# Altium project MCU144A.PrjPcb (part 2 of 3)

## Sheet MCU144A_SOM_Power.SchDoc: controlSOM Power
size 431 x 279 mm; Date: Not shown in title block; ApprovedBy: Not shown in title block; CheckedBy: Not shown in title block; Author: Not shown in title block; CompanyName: Not shown in title block; DrawnBy: Gustavo Martinez; Engineer: Not shown in title block; Organization: Not shown in title block; Address1: Not shown in title block; Address2: Not shown in title block; Address3: Not shown in title block; Address4: Not shown in title block; DocumentNumber: 6; Revision: Use project parameter SCH_Rev; SheetNumber: 5; SheetTotal: 8; PageSetup: Record=PageOptions¦CenterHorizontal=True¦CenterVertical=True¦PrintScale=1.00¦XCorrection=1.00¦YCorrection=1.00¦PrintKind=0¦BorderSize=5000000¦LeftOffset=0¦BottomOffset=0¦Orientation=2¦PaperLength=1000¦PaperWidth=1000¦Scale=100¦PaperSource=15¦PrintQuality=600¦MediaType=1¦DitherType=10¦PaperKind=Letter¦PrintScaleMode=1

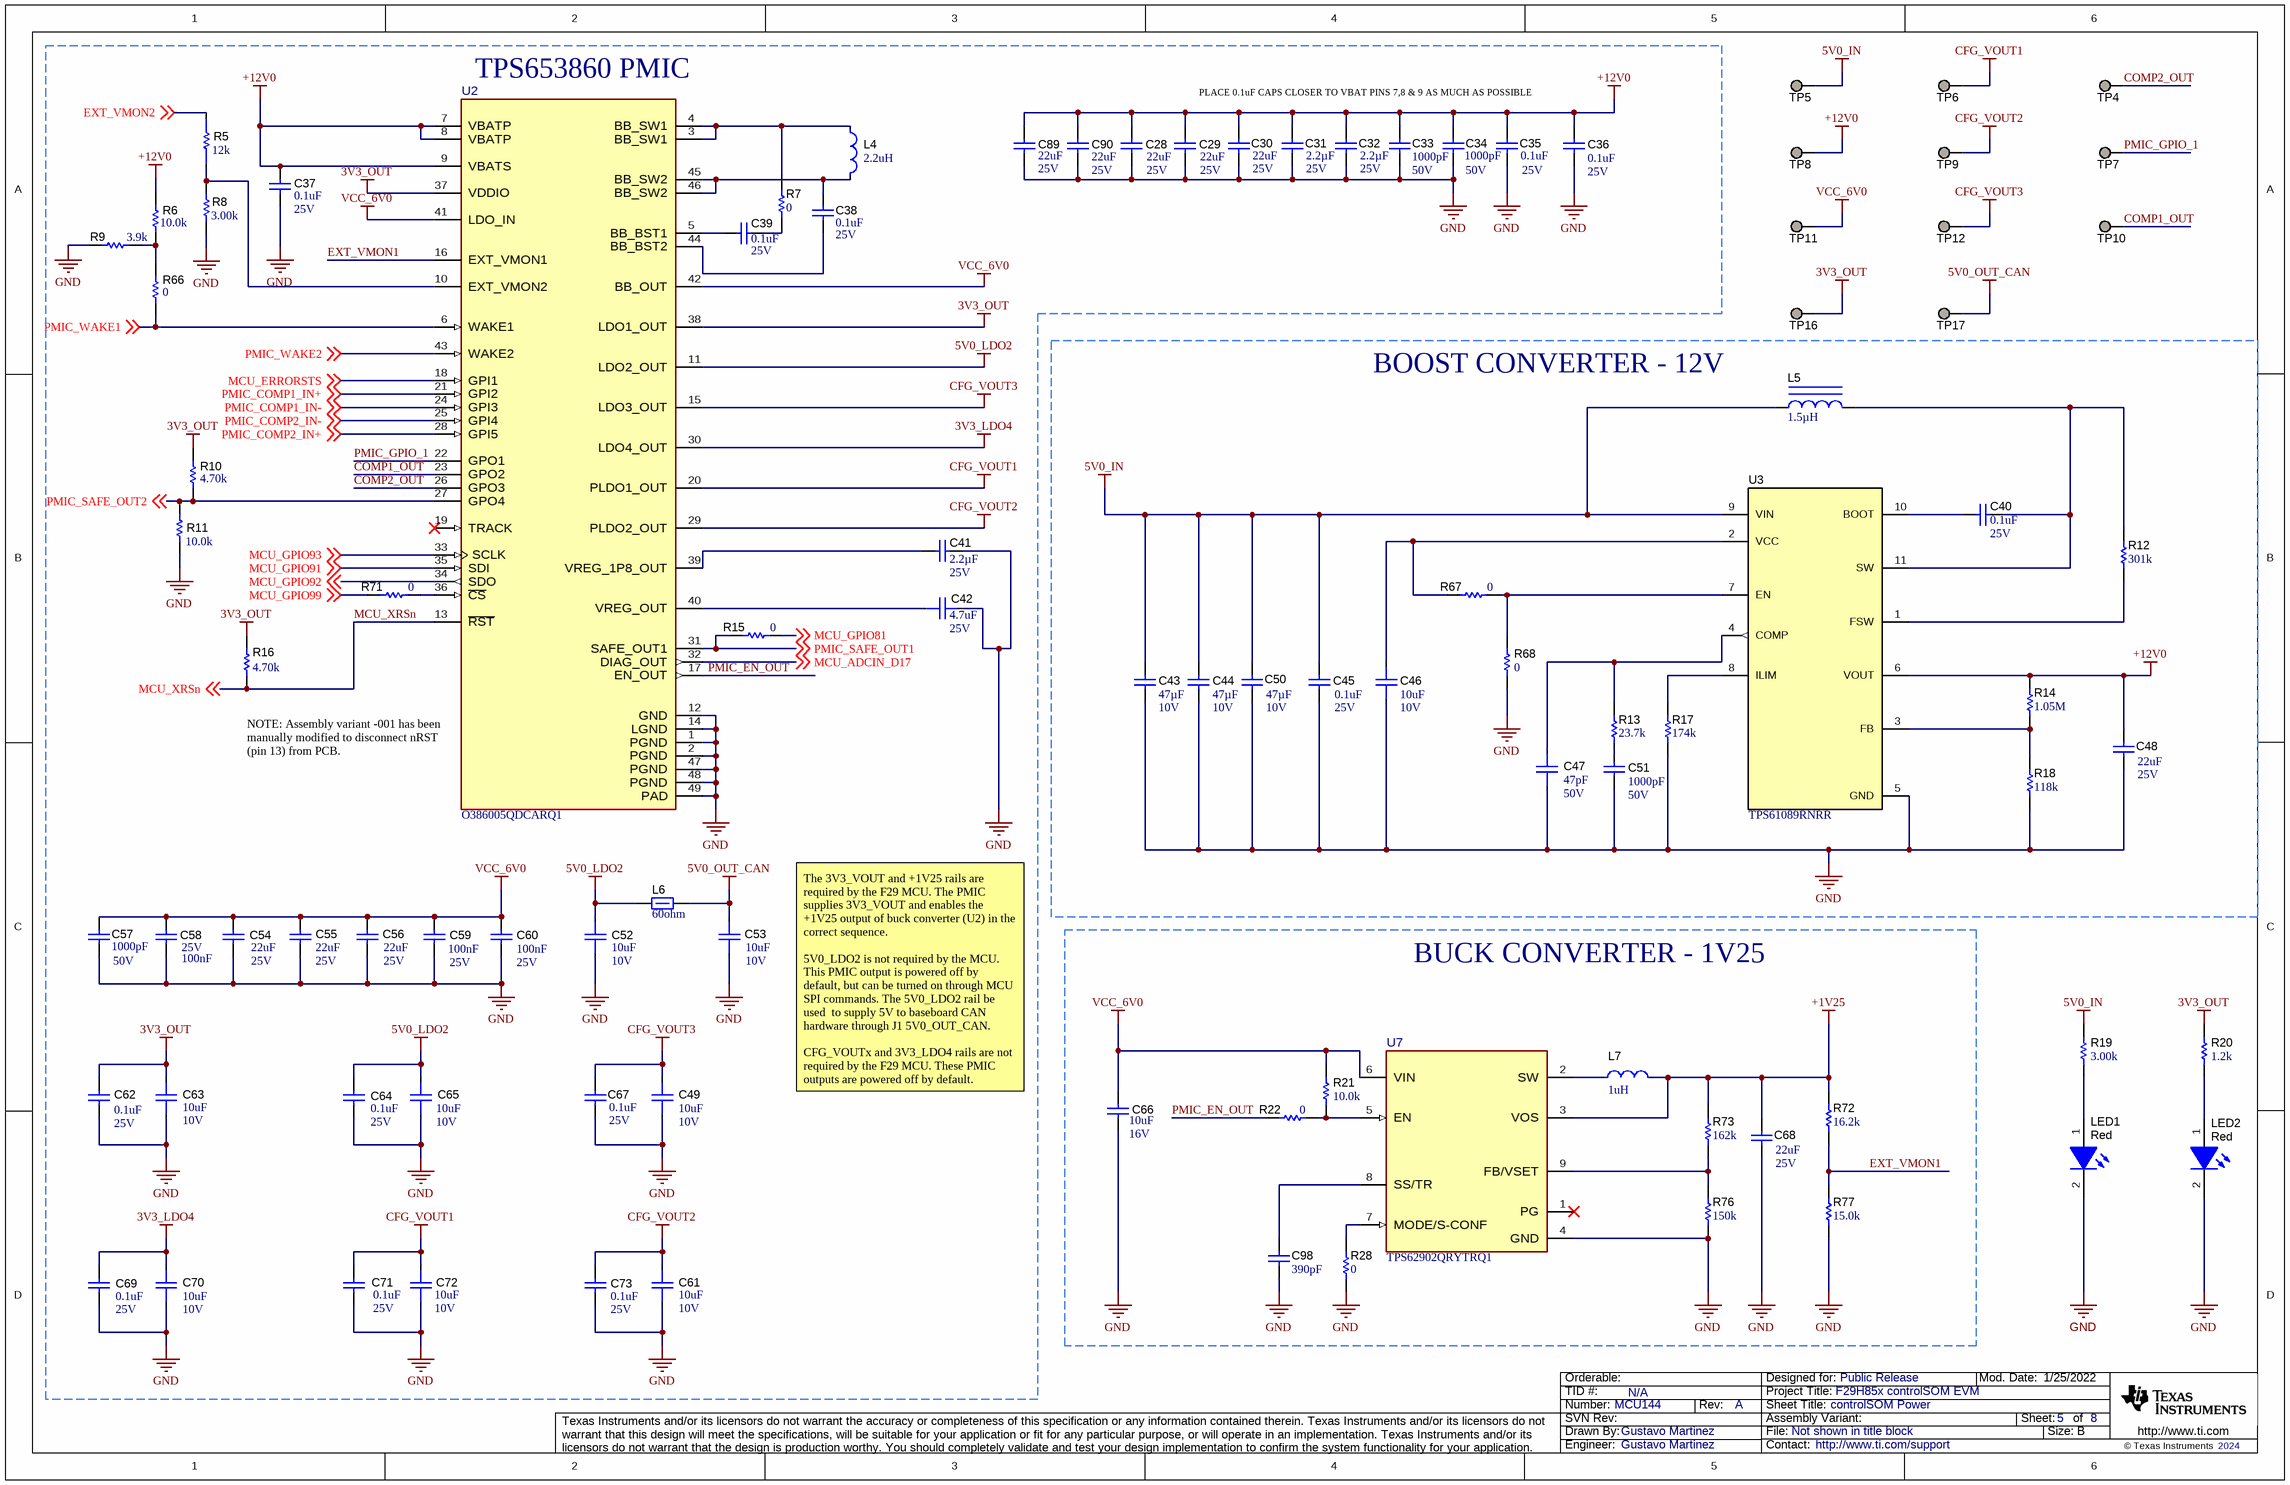
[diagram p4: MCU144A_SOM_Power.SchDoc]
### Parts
C28  VDC_V: 25V  ValueDisplayed: 22uF  [0805_HV]  (hidden comment: GRM21BR61E226ME44L)
C29  VDC_V: 25V  ValueDisplayed: 22uF  [0805_HV]  (hidden comment: GRM21BR61E226ME44L)
C30  VDC_V: 25V  ValueDisplayed: 22uF  [0805_HV]  (hidden comment: GRM21BR61E226ME44L)
C31  VDC_V: 25V  ValueDisplayed: 2.2µF  [0402]  (hidden comment: GRM155R61E225ME15D)
C32  VDC_V: 25V  ValueDisplayed: 2.2µF  [0402]  (hidden comment: GRM155R61E225ME15D)
C33  VDC_V: 50V  ValueDisplayed: 1000pF  [0402]  (hidden comment: GRM1555C1H102JA01D)
C34  VDC_V: 50V  ValueDisplayed: 1000pF  [0402]  (hidden comment: GRM1555C1H102JA01D)
C35  VDC_V: 25V  ValueDisplayed: 0.1uF  [0402]  (hidden comment: GRM155R71E104KE14D)
C36  VDC_V: 25V  ValueDisplayed: 0.1uF  [0402]  (hidden comment: GRM155R71E104KE14D)
C37  VDC_V: 25V  ValueDisplayed: 0.1uF  [0402]  (hidden comment: GRM155R71E104KE14D)
C38  VDC_V: 25V  ValueDisplayed: 0.1uF  [0402]  (hidden comment: GRM155R71E104KE14D)
C39  VDC_V: 25V  ValueDisplayed: 0.1uF  [0402]  (hidden comment: GRM155R71E104KE14D)
C40  Value2: 25V  ValueDisplayed: 0.1uF  [0402]  (hidden comment: GRM155R71E104KE14D)
C41  VDC_V: 25V  ValueDisplayed: 2.2µF  [0402]  (hidden comment: GRM155R61E225ME15D)
C42  ValueDisplayed: 4.7uF  VDC_V: 25V  [FP-GRM155C61E475ME15D_0402-MFG]  (hidden comment: GRM155C61E475ME15D)
C43  VDC_V: 10V  ValueDisplayed: 47µF  [0805_HV]  (hidden comment: GRM21BR61A476ME15L)
C44  VDC_V: 10V  ValueDisplayed: 47µF  [0805_HV]  (hidden comment: GRM21BR61A476ME15L)
C45  VDC_V: 25V  ValueDisplayed: 0.1uF  [0402]  (hidden comment: GRM155R71E104KE14D)
C46  VDC_V: 10V  ValueDisplayed: 10uF  [FP-GRM155R61A106ME18D_0402-MFG]  (hidden comment: GRM155R61A106ME18D)
C47  ValueDisplayed: 47pF  VDC_V: 50V  [FP-GJM1555C1H470JB01D_0402-MFG]  (hidden comment: GJM1555C1H470JB01D)
C48  VDC_V: 25V  ValueDisplayed: 22uF  [0805_HV]  (hidden comment: GRM21BR61E226ME44L)
C49  VDC_V: 10V  ValueDisplayed: 10uF  [FP-GRM155R61A106ME18D_0402-MFG]  (hidden comment: GRM155R61A106ME18D)
C50  VDC_V: 10V  ValueDisplayed: 47µF  [0805_HV]  (hidden comment: GRM21BR61A476ME15L)
C51  VDC_V: 50V  ValueDisplayed: 1000pF  [0402]  (hidden comment: GRM1555C1H102JA01D)
C52  VDC_V: 10V  ValueDisplayed: 10uF  [FP-GRM155R61A106ME18D_0402-MFG]  (hidden comment: GRM155R61A106ME18D)
C53  VDC_V: 10V  ValueDisplayed: 10uF  [FP-GRM155R61A106ME18D_0402-MFG]  (hidden comment: GRM155R61A106ME18D)
C54  VDC_V: 25V  ValueDisplayed: 22uF  [0805_HV]  (hidden comment: GRM21BR61E226ME44L)
C55  VDC_V: 25V  ValueDisplayed: 22uF  [0805_HV]  (hidden comment: GRM21BR61E226ME44L)
C56  VDC_V: 25V  ValueDisplayed: 22uF  [0805_HV]  (hidden comment: GRM21BR61E226ME44L)
C57  VDC_V: 50V  ValueDisplayed: 1000pF  [0402]  (hidden comment: GRM1555C1H102JA01D)
C58  Cap_F: 100nF  VDC_V: 25V  [0402]  (hidden comment: GRM155R71E104KE14D)
C59  Cap_F: 100nF  VDC_V: 25V  [0402]  (hidden comment: GRM155R71E104KE14D)
C60  Cap_F: 100nF  VDC_V: 25V  [0402]  (hidden comment: GRM155R71E104KE14D)
C61  VDC_V: 10V  ValueDisplayed: 10uF  [FP-GRM155R61A106ME18D_0402-MFG]  (hidden comment: GRM155R61A106ME18D)
C62  VDC_V: 25V  ValueDisplayed: 0.1uF  [0402]  (hidden comment: GRM155R71E104KE14D)
C63  VDC_V: 10V  ValueDisplayed: 10uF  [FP-GRM155R61A106ME18D_0402-MFG]  (hidden comment: GRM155R61A106ME18D)
C64  VDC_V: 25V  ValueDisplayed: 0.1uF  [0402]  (hidden comment: GRM155R71E104KE14D)
C65  VDC_V: 10V  ValueDisplayed: 10uF  [FP-GRM155R61A106ME18D_0402-MFG]  (hidden comment: GRM155R61A106ME18D)
C66  VDC_V: 16V  ValueDisplayed: 10uF  [0603]  (hidden comment: GRM188R61C106MAALD)
C67  VDC_V: 25V  ValueDisplayed: 0.1uF  [0402]  (hidden comment: GRM155R71E104KE14D)
C68  VDC_V: 25V  ValueDisplayed: 22uF  [0805_HV]  (hidden comment: GRM21BR61E226ME44L)
C69  VDC_V: 25V  ValueDisplayed: 0.1uF  [0402]  (hidden comment: GRM155R71E104KE14D)
C70  VDC_V: 10V  ValueDisplayed: 10uF  [FP-GRM155R61A106ME18D_0402-MFG]  (hidden comment: GRM155R61A106ME18D)
C71  VDC_V: 25V  ValueDisplayed: 0.1uF  [0402]  (hidden comment: GRM155R71E104KE14D)
C72  VDC_V: 10V  ValueDisplayed: 10uF  [FP-GRM155R61A106ME18D_0402-MFG]  (hidden comment: GRM155R61A106ME18D)
C73  VDC_V: 25V  ValueDisplayed: 0.1uF  [0402]  (hidden comment: GRM155R71E104KE14D)
C89  VDC_V: 25V  ValueDisplayed: 22uF  [0805_HV]  (hidden comment: GRM21BR61E226ME44L)
C90  VDC_V: 25V  ValueDisplayed: 22uF  [0805_HV]  (hidden comment: GRM21BR61E226ME44L)
C98  ValueDisplayed: 390pF  [0402]  (hidden comment: GCM155R71H391KA37D)
L4  value 2.2uH  [FP-SPM7054VT-2R2M-D_SMT_IND_7MM5_7MM0-MFG]  (hidden comment: SPM7054VT-2R2M-D)
L5  ValueDisplayed: 1.5µH  [DFE252012P]  (hidden comment: DFE252012P-1R5M=P2)
L6  60ohm  [0603]
L7  value 1uH  [FP-XGL4030-102MEC_SMD_IND_4MM0_4MM0-MFG]  (hidden comment: XGL4030-102MEC)
LED1  value Red  [APHHS1005_Red]  (hidden comment: APHHS1005SURCK)
LED2  value Red  [APHHS1005_Red]  (hidden comment: APHHS1005SURCK)
R5  value 12k  [FP-RC0402FR-0712KL_0402 (1005 Metric)-MFG]  (hidden comment: RC0402FR-0712KL)
R6  ValueDisplayed: 10.0k  [0402]  (hidden comment: AC0402FR-0710KL)
R7  ValueDisplayed: 0  [0402]  (hidden comment: CRCW04020000Z0ED)
R8  ValueDisplayed: 3.00k  [0402]  (hidden comment: RC0402FR-073KL)
R9  ValueDisplayed: 3.9k  [0402]  (hidden comment: CRCW04023K90JNED)
R10  value 4.70k  [0402]  (hidden comment: CRG0402F4K7)
R11  value 10.0k  [0402]  (hidden comment: AC0402FR-0710KL)
R12  ValueDisplayed: 301k  [0402]  (hidden comment: CRCW0402301KFKED)
R13  ValueDisplayed: 23.7k  [0402]  (hidden comment: CRCW040223K7FKED)
R14  ValueDisplayed: 1.05M  [0402]  (hidden comment: CRCW04021M05FKED)
R15  ValueDisplayed: 0  [0402]  (hidden comment: CRCW04020000Z0ED)
R16  ValueDisplayed: 4.70k  [0402]  (hidden comment: CRG0402F4K7)
R17  ValueDisplayed: 174k  [0402]  (hidden comment: CRCW0402174KFKED)
R18  ValueDisplayed: 118k  [0402]  (hidden comment: CRCW0402118KFKED)
R19  ValueDisplayed: 3.00k  [0402]  (hidden comment: RC0402FR-073KL)
R20  ValueDisplayed: 1.2k  [0402]  (hidden comment: CRCW04021K20JNED)
R21  value 10.0k  [0402]  (hidden comment: AC0402FR-0710KL)
R22  ValueDisplayed: 0  [0402]  (hidden comment: CRCW04020000Z0ED)
R28  ValueDisplayed: 0  [0402]  (hidden comment: CRCW04020000Z0ED)
R66  ValueDisplayed: 0  [0402]  (hidden comment: CRCW04020000Z0ED)
R67  ValueDisplayed: 0  [0402]  (hidden comment: CRCW04020000Z0ED)
R68  value 0  [0402]  (hidden comment: CRCW04020000Z0ED)
R71  ValueDisplayed: 0  [0402]  (hidden comment: CRCW04020000Z0ED)
R72  ValueDisplayed: 16.2k  [0402]  (hidden comment: CRCW040216K2FKED)
R73  ValueDisplayed: 162k  [0402]  (hidden comment: CRCW0402162KFKED)
R76  ValueDisplayed: 150k  [0402]  (hidden comment: CRCW0402150KFKED)
R77  ValueDisplayed: 15.0k  [0402]  (hidden comment: CRCW040215K0FKED)
TP4  TP_SM_1MM  [TP_SM_1MM]  (value not drawn)  (no BOM)
TP5  CMP-0078143-4  [TESTPOINT]  (value not drawn)  (no BOM)
TP6  TP_SM_1MM  [TP_SM_1MM]  (value not drawn)  (no BOM)
TP7  TP_SM_1MM  [TP_SM_1MM]  (value not drawn)  (no BOM)
TP8  CMP-0078143-4  [TESTPOINT]  (value not drawn)  (no BOM)
TP9  TP_SM_1MM  [TP_SM_1MM]  (value not drawn)  (no BOM)
TP10  TP_SM_1MM  [TP_SM_1MM]  (value not drawn)  (no BOM)
TP11  TP_SM_1MM  [TP_SM_1MM]  (value not drawn)  (no BOM)
TP12  TP_SM_1MM  [TP_SM_1MM]  (value not drawn)  (no BOM)
TP16  CMP-0078143-4  [TESTPOINT]  (value not drawn)  (no BOM)
TP17  CMP-0078143-4  [TESTPOINT]  (value not drawn)  (no BOM)
U2  O386005QDCARQ1  [DCA0048J-MFG]
U3  TPS61089RNRR  [RNR0011A]
U7  TPS62902QRYTRQ1  [RYT0009A-MFG]

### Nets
3V3_LDO4: C69.1 C70.2 U2.30(LDO4_OUT)
3V3_OUT: C62.1 C63.2 R10.2 R16.2 R20.2 TP16.1 U2.37(VDDIO) U2.38(LDO1_OUT)
5V0_IN: C43.1 C44.1 C45.1 C50.1 L5.1 R19.2 TP5.1 U3.9(VIN)
5V0_LDO2: C52.2 C64.1 C65.2 L6.1 U2.11(LDO2_OUT)
5V0_OUT_CAN: C53.2 L6.2 TP17.1
+1V25: C68.1 L7.2 R72.2 R73.2 U7.3(VOS)
+12V0: C28.1 C29.1 C30.1 C31.1 C32.1 C33.1 C34.1 C35.1 C36.1 C37.1 C48.1 C89.1 C90.1 R6.2 R14.2 TP8.1 U2.7(VBATP) U2.8(VBATP) U2.9(VBATS) U3.6(VOUT)
CFG_VOUT1: C71.1 C72.2 TP6.1 U2.20(PLDO1_OUT)
CFG_VOUT2: C61.2 C73.1 TP9.1 U2.29(PLDO2_OUT)
CFG_VOUT3: C49.2 C67.1 TP12.1 U2.15(LDO3_OUT)
GND: C28.2 C29.2 C30.2 C31.2 C32.2 C33.2 C34.2 C35.2 C36.2 C37.2 C41.1 C42.2 C43.2 C44.2 C45.2 C46.1 C47.1 C48.2 C49.1 C50.2 C51.2 C52.1 C53.1 C54.2 C55.2 C56.2 C57.2 C58.2 C59.2 C60.2 C61.1 C62.2 C63.1 C64.2 C65.1 C66.2 C67.2 C68.2 C69.2 C70.1 C71.2 C72.1 C73.2 C89.2 C90.2 C98.1 LED1.2(K) LED2.2(K) R8.1 R9.1 R11.1 R17.1 R18.1 R28.1 R68.1 R76.1 R77.1 U2.1(PGND) U2.2(PGND) U2.12(GND) U2.14(LGND) U2.47(PGND) U2.48(PGND) U2.49(PAD) U3.5(GND) U7.4(GND)
VCC_6V0: C54.1 C55.1 C56.1 C57.1 C58.1 C59.1 C60.1 C66.1 R21.2 TP11.1 U2.41(LDO_IN) U2.42(BB_OUT) U7.6(VIN)
COMP1_OUT: TP10.1 U2.23(GPO2)
COMP2_OUT: TP4.1 U2.26(GPO3)
EXT_VMON1: R72.1 R77.2 U2.16(EXT_VMON1)
EXT_VMON2: R5.2 ; off-sheet EXT_VMON2
MCU_ADCIN_D17: U2.32(DIAG_OUT) ; off-sheet MCU_ADCIN_D17
MCU_ERRORSTS: U2.18(GPI1) ; off-sheet MCU_ERRORSTS
MCU_GPIO81: R15.2 ; off-sheet MCU_GPIO81
MCU_GPIO91: U2.35(SDI) ; off-sheet MCU_GPIO91
MCU_GPIO92: U2.34(SDO) ; off-sheet MCU_GPIO92
MCU_GPIO93: U2.33(SCLK) ; off-sheet MCU_GPIO93
MCU_GPIO99: R71.1 ; off-sheet MCU_GPIO99
MCU_XRSn: R16.1 U2.13(~{RST}) ; off-sheet MCU_XRSn
PMIC_COMP1_IN+: U2.21(GPI2) ; off-sheet PMIC_COMP1_IN+
PMIC_COMP1_IN-: U2.24(GPI3) ; off-sheet PMIC_COMP1_IN-
PMIC_COMP2_IN+: U2.28(GPI5) ; off-sheet PMIC_COMP2_IN+
PMIC_COMP2_IN-: U2.25(GPI4) ; off-sheet PMIC_COMP2_IN-
PMIC_EN_OUT: R22.1 U2.17(EN_OUT)
PMIC_GPIO_1: TP7.1 U2.22(GPO1)
PMIC_SAFE_OUT1: R15.1 U2.31(SAFE_OUT1) ; off-sheet PMIC_SAFE_OUT1
PMIC_SAFE_OUT2: R10.1 R11.2 U2.27(GPO4) ; off-sheet PMIC_SAFE_OUT2
PMIC_WAKE1: R66.1 U2.6(WAKE1) ; off-sheet PMIC_WAKE1
PMIC_WAKE2: U2.43(WAKE2) ; off-sheet PMIC_WAKE2
NetC38_1: C38.1 L4.2 U2.45(BB_SW2) U2.46(BB_SW2)
NetC38_2: C38.2 U2.44(BB_BST2)
NetC39_1: C39.1 R7.1
NetC39_2: C39.2 U2.5(BB_BST1)
NetC40_1: C40.1 U3.10(BOOT)
NetC40_2: C40.2 L5.2 R12.2 U3.11(SW)
NetC41_2: C41.2 U2.39(VREG_1P8_OUT)
NetC42_1: C42.1 U2.40(VREG_OUT)
NetC46_2: C46.2 R67.2 U3.2(VCC)
NetC47_2: C47.2 R13.2 U3.4(COMP)
NetC51_1: C51.1 R13.1
NetC98_2: C98.2 U7.8(SS/TR)
NetL4_1: L4.1 R7.2 U2.3(BB_SW1) U2.4(BB_SW1)
NetL7_1: L7.1 U7.2(SW)
NetLED1_1: LED1.1(A) R19.1
NetLED2_1: LED2.1(A) R20.1
NetR5_1: R5.1 R8.2 U2.10(EXT_VMON2)
NetR6_1: R6.1 R9.2 R66.2
NetR12_1: R12.1 U3.1(FSW)
NetR14_1: R14.1 R18.2 U3.3(FB)
NetR17_2: R17.2 U3.8(ILIM)
NetR21_1: R21.1 R22.2 U7.5(EN)
NetR28_2: R28.2 U7.7(MODE/S-CONF)
NetR67_1: R67.1 R68.2 U3.7(EN)
NetR71_2: R71.2 U2.36(~{CS})
NetR73_1: R73.1 R76.2 U7.9(FB/VSET)

Not connected (* = marked no-connect by the designer): U2 19(TRACK)*; U7 1(PG)*

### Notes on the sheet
- (near U2) TPS653860 PMIC
- PLACE 0.1uF CAPS CLOSER TO VBAT PINS 7,8 & 9 AS MUCH AS POSSIBLE
- BOOST CONVERTER - 12V
- (near R71) MCU_XRSn
- (near U2) NOTE: Assembly variant -001 has been manually modified to disconnect nRST (pin 13) from PCB.
- BUCK CONVERTER - 1V25
- The 3V3_VOUT and +1V25 rails are required by the F29 MCU. The PMIC supplies 3V3_VOUT and enables the +1V25 output of buck converter (U2) in the correct sequence.
  5V0_LDO2 is not required by the MCU. This PMIC output is powered off by default, but can be turned on through MCU SPI commands. The 5V0_LDO2 rail be used  to supply 5V to baseboard CAN hardware through J1 5V0_OUT_CAN.
  CFG_VOUTx and 3V3_LDO4 rails are not required by the F29 MCU. These PMIC outputs are powered off by default.

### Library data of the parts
C28-C30 C48 C68 C89 C90 = CMP-0008305-2: CAP, CERM, 22 uF, 25 V, +/- 20%, X5R, 0805; Manufacturer: MuRata; TaMin_C: -55°C; Polarized: N; SizeAreaWB_mm2: 6.75; Value1: Unknown; U/M: EA; Value: 22uF; TaMax_C: 85°C; SizeZ_mm: 1.45; SizeX_mm: 2; SizeY_mm: 1.25; Cap_Case: 0805; SizeArea_mm2: 2.5; Cap_F: 22µF; AEC Category: Q200
C31 C32 C41 = CMP-0081010-1: CAP, CERM, 2.2 µF, 25 V,+/- 20%, X5R, 0402; Manufacturer: MuRata; SizeAreaWB_mm2: 3; SizeArea_mm2: 0.5; AEC Qualified: N; AEC Category: Q200; Value: 2.2uF; TaMax_C: 85°C; SizeZ_mm: 0.6; TaMin_C: -55°C; U/M: EA; SizeX_mm: 1
C33 C34 C51 C57 = CMP-0006412-2: CAP, CERM, 1000 pF, 50 V, +/- 5%, C0G/NP0, 0402; Manufacturer: MuRata; TaMin_C: -55°C; Polarized: N; SizeAreaWB_mm2: 3; Value1: Unknown; U/M: EA; Value: 1000pF; TaMax_C: 125°C; SizeZ_mm: 0.6; SizeX_mm: 1; SizeY_mm: 0.5; Cap_F: 1nF; AEC Category: Q200
C35-C40 C45 C62 C64 C67 C69 C71 C73 = CMP-0006659-2: CAP, CERM, 0.1 uF, 25 V, +/- 10%, X7R, 0402; Manufacturer: MuRata; TaMin_C: -55°C; Polarized: N; SizeAreaWB_mm2: 3; Value1: Unknown; U/M: EA; Value: 0.1uF; TaMax_C: 125°C; SizeZ_mm: 0.6; SizeX_mm: 1; SizeY_mm: 0.5; Cap_F: 100nF; AEC Category: Q200
C42 = CMP-0120206-1: 4.7 µF ±20% 25V Ceramic Capacitor X5S 0402 (1005 Metric); Manufacturer: Murata; AEC Qualified: No; Cap_F: 4.7µF; SizeZ_mm: 0.7mm; TempCo: 22%; Value: 4.7µF
C43 C44 C50 = CMP-0078699-1: CAP, CERM, 47 µF, 10 V,+/- 20%, X5R, 0805; Manufacturer: MuRata; TaMin_C: -55°C; Polarized: N; Green_Lifecycle: Active; SizeAreaWB_mm2: 6.75; Green_REACh: Passed; U/M: EA; Value: 47uF; TaMax_C: 85°C; SizeZ_mm: 1.45; SizeX_mm: 2; SizeY_mm: 1.25; Cap_Case: 0805; SizeArea_mm2: 2.5; AEC Category: Q200
C46 C49 C52 C53 C61 C63 C65 C70 C72 = CMP-0120207-1: 10 µF ±20% 10V Ceramic Capacitor X5R 0402 (1005 Metric); Manufacturer: Murata; Cap_F: 10µF; TempCo: 15%; SizeZ_mm: 0.7mm; Value: 10µF; AEC Qualified: No
C47 = CMP-0120205-1: Multi-Layer Ceramic Capacitor 47pF C0G  ±5% 0402 Paper T/R; Manufacturer: Murata; AEC Qualified: No; SizeZ_mm: 0.55mm; TempCo: 30ppm/°C
C54-C56 = CMP-0008305-2: CAP, CERM, 22 uF, 25 V, +/- 20%, X5R, 0805; Manufacturer: MuRata; SizeZ_mm: 1.45; AEC Qualified: N; Value: 22uF; Cap_F: 22µF; AEC Category: Q200; Cap_Case: 0805; SizeArea_mm2: 2.5; SizeAreaWB_mm2: 6.75; SizeX_mm: 2; SizeY_mm: 1.25; TaMax_C: 85°C; TaMin_C: -55°C; U/M: EA; Value1: Unknown
C58-C60 = CMP-0006659-2: CAP, CERM, 0.1 uF, 25 V, +/- 10%, X7R, 0402; Manufacturer: MuRata; TaMin_C: -55°C; Polarized: N; SizeAreaWB_mm2: 3; Value1: Unknown; U/M: EA; Value: 0.1uF; TaMax_C: 125°C; SizeZ_mm: 0.6; SizeX_mm: 1; SizeY_mm: 0.5; AEC Category: Q200
C66 = CMP-0007336-5: CAP, CERM, 10 uF, 16 V, +/- 20%, X5R, 0603; Manufacturer: MuRata; TaMin_C: -55°C; Polarized: N; SizeAreaWB_mm2: 4.68; Value1: Unknown; U/M: EA; Value: 10uF; TaMax_C: 85°C; SizeZ_mm: 1; SizeX_mm: 1.6; SizeY_mm: 0.8; SizeArea_mm2: 1.28; Cap_F: 10µF; AEC Category: Q200
C98 = CMP-0080703-2: CAP, CERM, 390 pF, 50 V,+/- 10%, X7R, AEC-Q200 Grade 1, 0402; Manufacturer: MuRata; SizeX_mm: 1; SizeZ_mm: 0.6; SizeY_mm: 0.5; AEC Qualified: Y; Value: 390pF; Polarized: N; AEC Category: Q200; TaMax_C: 125°C; VDC_V: 50V; TaMin_C: -55°C; SizeAreaWB_mm2: 3; U/M: EA
L4 = CMP-0096709-1: Inductor Power Shielded Wirewound 2.2uH 20% 100KHz Metal 12A 0.00814Ohm DCR Automotive T/R; Manufacturer: TDK; Ind_H: 2.2µH; AEC Grade: Grade 0; Isat: 14.1A; SizeZ_mm: 5.4mm; AEC Qualified: Yes; Shrouded: true; Material: Metal Composite; DCR_ohm: 8.14m
L5 = CMP-0082609-1: Inductor, Shielded, Metal Composite, 1.5 µH, 2.6 A, 0.06 ohm, SMD; Manufacturer: MuRata; Isat: 3.5A @ 30% inductance drop; Irms: 2.6A @ 40C rise; SizeAreaWB_mm2: 10.5; DCR_ohm: 0.06; Value: 1.5uH; Imax_A: 2.6A; SizeZ_mm: 1.2; SizeX_mm: 2.5; SizeY_mm: 2; SizeArea_mm2: 5; AEC Qualified: N; AEC Category: Q200
L6 = CMP-0003173-2: Ferrite Bead, 60 ohm @ 100 MHz, 3 A, 0603; Manufacturer: Wurth Elektronik; PartNumber: 742792602; Ztyp@1GHz_Ohm: 110.436; ZTyp@100MHz_Ohm: 60; SizeAreaWB_mm2: 4.68; DCR_ohm: 0.04; Value1: 0.04 ohm; Imax_A: 3A; SizeZ_mm: 1; SizeX_mm: 1.6; SizeY_mm: 0.8; SizeArea_mm2: 1.28
L7 = CMP-0090842-1: Power Inductor, shielded, composite, 1uH 20% tol, DCR 7.2mOhms, SRF 65MHz, Isat 4.8A, Irms 13A, AEC-Q200; Manufacturer: Coilcraft; TaMin_C: -40°C; TaMax_C: +125°C; Test Frequency: 1MHz; DCR_ohm: 7.2m; AEC Grade: Grade 1; SizeZ_mm: 3.1mm; AEC Qualified: Yes; Shrouded: true; Ind_H: 1µH
LED1 LED2 = CMP-0067681-2: LED, Red, SMD; Manufacturer: Kingbright; Vf_V: 1.95V; SizeAreaWB_mm2: 3.0; Tjmax_C: 85°C; SizeX_mm: 1.0; Io_A: 20mA; SizeArea_mm2: 0.5; Vr_V: 5V; Value1: 0.075W; SizeZ_mm: 0.6; Angle: 120.0; Ir_A: 10µA; Power_TotalModule: 75mW
R5 = CMP-0092615-1: 12 kOhms ±1% 0.063W, 1/16W Chip Resistor 0402 (1005 Metric) Moisture Resistant Thick Film; Manufacturer: Yageo; SizeZ_mm: 0.4mm; VDC_V: 50V; TempCo: 100ppm/°C; AEC Qualified: No; Power_W: 63mW
R6 = CMP-0077731-1: RES, 10.0 k, 1%, 0.063 W, AEC-Q200 Grade 0, 0402; Manufacturer: Yageo America; Power_W: 63mW; TempCo: 100 ppm/C; Value_Code: 10k0; U/M: EA; Value: 10.0k; EIA_Code: E96; Res_ohm: 10k; SizeX_mm: 1.0; SizeY_mm: 0.5; SizeZ_mm: 0.6; Value2: 0.063W; AEC Qualified: Y; VDC_V: 50V; AEC Grade: 0; AEC Category: Q200
R7 R15 R22 R28 R66 R67 R71 = CMP-0026822-3: RES, 0, 5%, 0.063 W, AEC-Q200 Grade 0, 0402; Manufacturer: Vishay-Dale; Power_W: 63mW; TempCo: 200 ppm/C; Value_Code: 0000; Value: 0; EIA_Code: E24; SizeX_mm: 1; SizeY_mm: 0.5; SizeZ_mm: 0.6; Value2: 0.063W; AEC Qualified: Y; VDC_V: 50V; AEC Category: Q200
R8 R19 = CMP-0026733-1: RES, 3.00 k, 1%, 0.0625 W, 0402; Manufacturer: Yageo America; Power_W: 62.5mW; TempCo: 100 ppm/C; Value_Code: 3k00; U/M: EA; Value: 3.00k; Res_ohm: 3k; SizeX_mm: 1; SizeY_mm: 0.5; SizeZ_mm: 0.6; AEC Qualified: N; VDC_V: 50V; AEC Category: Q200
R9 = CMP-0026920-5: RES, 3.9 k, 5%, 0.063 W, AEC-Q200 Grade 0, 0402; Manufacturer: Vishay-Dale; Power_W: 63mW; TempCo: 200 ppm/C; Value_Code: 3k90; Value: 3.9k; EIA_Code: E24; SizeX_mm: 1; SizeY_mm: 0.5; SizeZ_mm: 0.6; Value2: 0.063W; AEC Qualified: Y; VDC_V: 50V; AEC Category: Q200; AEC Grade: 0
R10 = CMP-0026631-1: RES, 4.70 k, 1%, 0.063 W, 0402; Manufacturer: TE Connectivity; Power_W: 63mW; TempCo: 100 ppm/C; Value_Code: 4k70; U/M: EA; Res_ohm: 4.7k; SizeX_mm: 1; SizeY_mm: 0.5; SizeZ_mm: 0.6; Value2: 0.063W; AEC Qualified: N; AEC Category: Q200
R11 R21 = CMP-0077731-1: RES, 10.0 k, 1%, 0.063 W, AEC-Q200 Grade 0, 0402; Manufacturer: Yageo America; Power_W: 63mW; TempCo: 100 ppm/C; Value_Code: 10k0; U/M: EA; EIA_Code: E96; Res_ohm: 10k; SizeX_mm: 1.0; SizeY_mm: 0.5; SizeZ_mm: 0.6; Value2: 0.063W; AEC Qualified: Y; VDC_V: 50V; AEC Grade: 0; AEC Category: Q200
R12 = CMP-0026280-2: RES, 301 k, 1%, 0.063 W, AEC-Q200 Grade 0, 0402; Manufacturer: Vishay-Dale; Power_W: 63mW; TempCo: 100 ppm/C; Value: 301k; EIA_Code: E96; SizeX_mm: 1; SizeY_mm: 0.5; SizeZ_mm: 0.6; Value2: 0.063W; AEC Qualified: Y; VDC_V: 50V; AEC Category: Q200; AEC Grade: 0
R13 = CMP-0026187-2: RES, 23.7 k, 1%, 0.063 W, AEC-Q200 Grade 0, 0402; Manufacturer: Vishay-Dale; Power_W: 63mW; TempCo: 100 ppm/C; Value_Code: 23k7; Value: 23.7k; EIA_Code: E96; SizeX_mm: 1; SizeY_mm: 0.5; SizeZ_mm: 0.6; Value2: 0.063W; AEC Qualified: Y; VDC_V: 50V; AEC Category: Q200; AEC Grade: 0
R14 = CMP-0026102-2: RES, 1.05 M, 1%, 0.063 W, AEC-Q200 Grade 0, 0402; Manufacturer: Vishay-Dale; Power_W: 63mW; TempCo: 100 ppm/C; Value_Code: 1M05; Value: 1.05Meg; EIA_Code: E96; SizeX_mm: 1; SizeY_mm: 0.5; SizeZ_mm: 0.6; Value2: 0.063W; AEC Qualified: Y; VDC_V: 50V; AEC Category: Q200; AEC Grade: 0
R16 = CMP-0026631-1: RES, 4.70 k, 1%, 0.063 W, 0402; Manufacturer: TE Connectivity; Power_W: 63mW; TempCo: 100 ppm/C; Value_Code: 4k70; U/M: EA; Value: 4.70k; Res_ohm: 4.7k; SizeX_mm: 1; SizeY_mm: 0.5; SizeZ_mm: 0.6; Value2: 0.063W; AEC Qualified: N; AEC Category: Q200
R17 = CMP-0026046-3: RES, 174 k, 1%, 0.063 W, AEC-Q200 Grade 0, 0402; Manufacturer: Vishay-Dale; Power_W: 63mW; TempCo: 100 ppm/C; Value: 174k; EIA_Code: E96; SizeX_mm: 1; SizeY_mm: 0.5; SizeZ_mm: 0.6; Value2: 0.063W; AEC Qualified: Y; VDC_V: 50V; AEC Category: Q200; AEC Grade: 0
R18 = CMP-0025973-3: RES, 118 k, 1%, 0.063 W, AEC-Q200 Grade 0, 0402; Manufacturer: Vishay-Dale; Power_W: 63mW; TempCo: 100 ppm/C; Value: 118k; EIA_Code: E96; SizeX_mm: 1; SizeY_mm: 0.5; SizeZ_mm: 0.6; Value2: 0.063W; AEC Qualified: Y; VDC_V: 50V; AEC Category: Q200; AEC Grade: 0
R20 = CMP-0026854-5: RES, 1.2 k, 5%, 0.063 W, AEC-Q200 Grade 0, 0402; Manufacturer: Vishay-Dale; Power_W: 63mW; TempCo: 200 ppm/C; Value_Code: 1k20; Value: 1.2k; EIA_Code: E24; SizeX_mm: 1; SizeY_mm: 0.5; SizeZ_mm: 0.6; Value2: 0.063W; AEC Qualified: Y; VDC_V: 50V; AEC Category: Q200; AEC Grade: 0
R68 = CMP-0026822-3: RES, 0, 5%, 0.063 W, AEC-Q200 Grade 0, 0402; Manufacturer: Vishay-Dale; Power_W: 63mW; TempCo: 200 ppm/C; Value_Code: 0000; EIA_Code: E24; SizeX_mm: 1; SizeY_mm: 0.5; SizeZ_mm: 0.6; Value2: 0.063W; AEC Qualified: Y; VDC_V: 50V; AEC Category: Q200
R72 = CMP-0026040-3: RES, 16.2 k, 1%, 0.063 W, AEC-Q200 Grade 0, 0402; Manufacturer: Vishay-Dale; Power_W: 63mW; TempCo: 100 ppm/C; Value_Code: 16k2; Value: 16.2k; EIA_Code: E96; SizeX_mm: 1; SizeY_mm: 0.5; SizeZ_mm: 0.6; Value2: 0.063W; AEC Qualified: Y; VDC_V: 50V; AEC Category: Q200; AEC Grade: 0
R73 = CMP-0026034-3: RES, 162 k, 1%, 0.063 W, AEC-Q200 Grade 0, 0402; Manufacturer: Vishay-Dale; Power_W: 63mW; TempCo: 100 ppm/C; Value: 162k; EIA_Code: E96; SizeX_mm: 1; SizeY_mm: 0.5; SizeZ_mm: 0.6; Value2: 0.063W; AEC Qualified: Y; VDC_V: 50V; AEC Category: Q200; AEC Grade: 0
R76 = CMP-0026021-3: RES, 150 k, 1%, 0.063 W, AEC-Q200 Grade 0, 0402; Manufacturer: Vishay-Dale; Power_W: 63mW; TempCo: 100 ppm/C; Value: 150k; EIA_Code: E96; SizeX_mm: 1; SizeY_mm: 0.5; SizeZ_mm: 0.6; Value2: 0.063W; AEC Qualified: Y; VDC_V: 50V; AEC Category: Q200; AEC Grade: 0
R77 = CMP-0026027-3: RES, 15.0 k, 1%, 0.063 W, AEC-Q200 Grade 0, 0402; Manufacturer: Vishay-Dale; Power_W: 63mW; TempCo: 100 ppm/C; Value_Code: 15k0; Value: 15.0k; EIA_Code: E96; Res_ohm: 15k; SizeX_mm: 1; SizeY_mm: 0.5; SizeZ_mm: 0.6; Value2: 0.063W; AEC Qualified: Y; VDC_V: 50V; AEC Category: Q200; AEC Grade: 0
TP4 TP6 TP7 TP9-TP12 = CMP-0003825-1: 1mm Test Point, SMT; Manufacturer: Any
TP5 TP8 TP16 TP17 = CMP-0078143-4: TEST POINT.  No entry in BOM.
U2 = CMP-0095884-2: Power Management IC For Safety-Relevant Applications HTSSOP48 5 Outputs 4 LDO and 1 Synchronous Buck-Boost Regulator; Manufacturer: Texas Instruments; SizeZ_mm: 1.2mm; AEC Qualified: Yes; Standoff Height: 0.05mm; Max Supply Voltage: 28V; TaMin_C: -40°C; AEC Grade: Grade 1; TJmax_C: +150°C; Min Supply Voltage: 2.3V; Number Of Outputs: 7; TaMax_C: +125°C; AEC Category: Q200
U3 = CMP-0074067-1: 12.6-V, 7-A Fully-Integrated Synchronous Boost Converters in 2.0-mm x 2.5-mm VQFN Package, RNR0011A (VQFN-HR-11); Alternate PartNumber: TPS61089RNRT; Alternate Manufacturer: Texas Instruments; SizeAreaWB_mm2: 10.5; U/M: EA; SizeZ_mm: 1.0; SizeX_mm: 2.5; SizeY_mm: 2.0; SizeArea_mm2: 5.0; CompType: IC
U7 = CMP-0121948-1: 3-V to 18-V, 2-A, Automotive Low IQ Buck Converter with +165°C TJ; Manufacturer: Texas Instruments; SizeZ_mm: 1.05mm; AEC Qualified: Yes; AEC Grade: Grade 1; Max Duty Cycle: 100%; Max Supply Voltage: 18V; Min Supply Voltage: 3V; Nominal Supply Current: 8mA; Number Of Outputs: 1; Output Type: AdjustableProgrammable; Output Voltage: 0.4-5.5V; Standoff Height: 0mm; Switching Frequency: 1/2.5MHz; TaMax_C: +125°C; TaMin_C: -40°C

## Sheet MCU144A_Baseboard_Connectors.SchDoc: Baseboard Connectors
size 431 x 279 mm; DrawnBy: Gustavo Martinez; DocumentNumber: 10; SheetNumber: 6; SheetTotal: 8; PageSetup: Record=PageOptions¦CenterHorizontal=True¦CenterVertical=True¦PrintScale=1.00¦XCorrection=1.00¦YCorrection=1.00¦PrintKind=0¦BorderSize=5000000¦LeftOffset=0¦BottomOffset=0¦Orientation=2¦PaperLength=1000¦PaperWidth=1000¦Scale=100¦PaperSource=15¦PrintQuality=600¦MediaType=1¦DitherType=10¦PaperKind=Letter¦PrintScaleMode=1

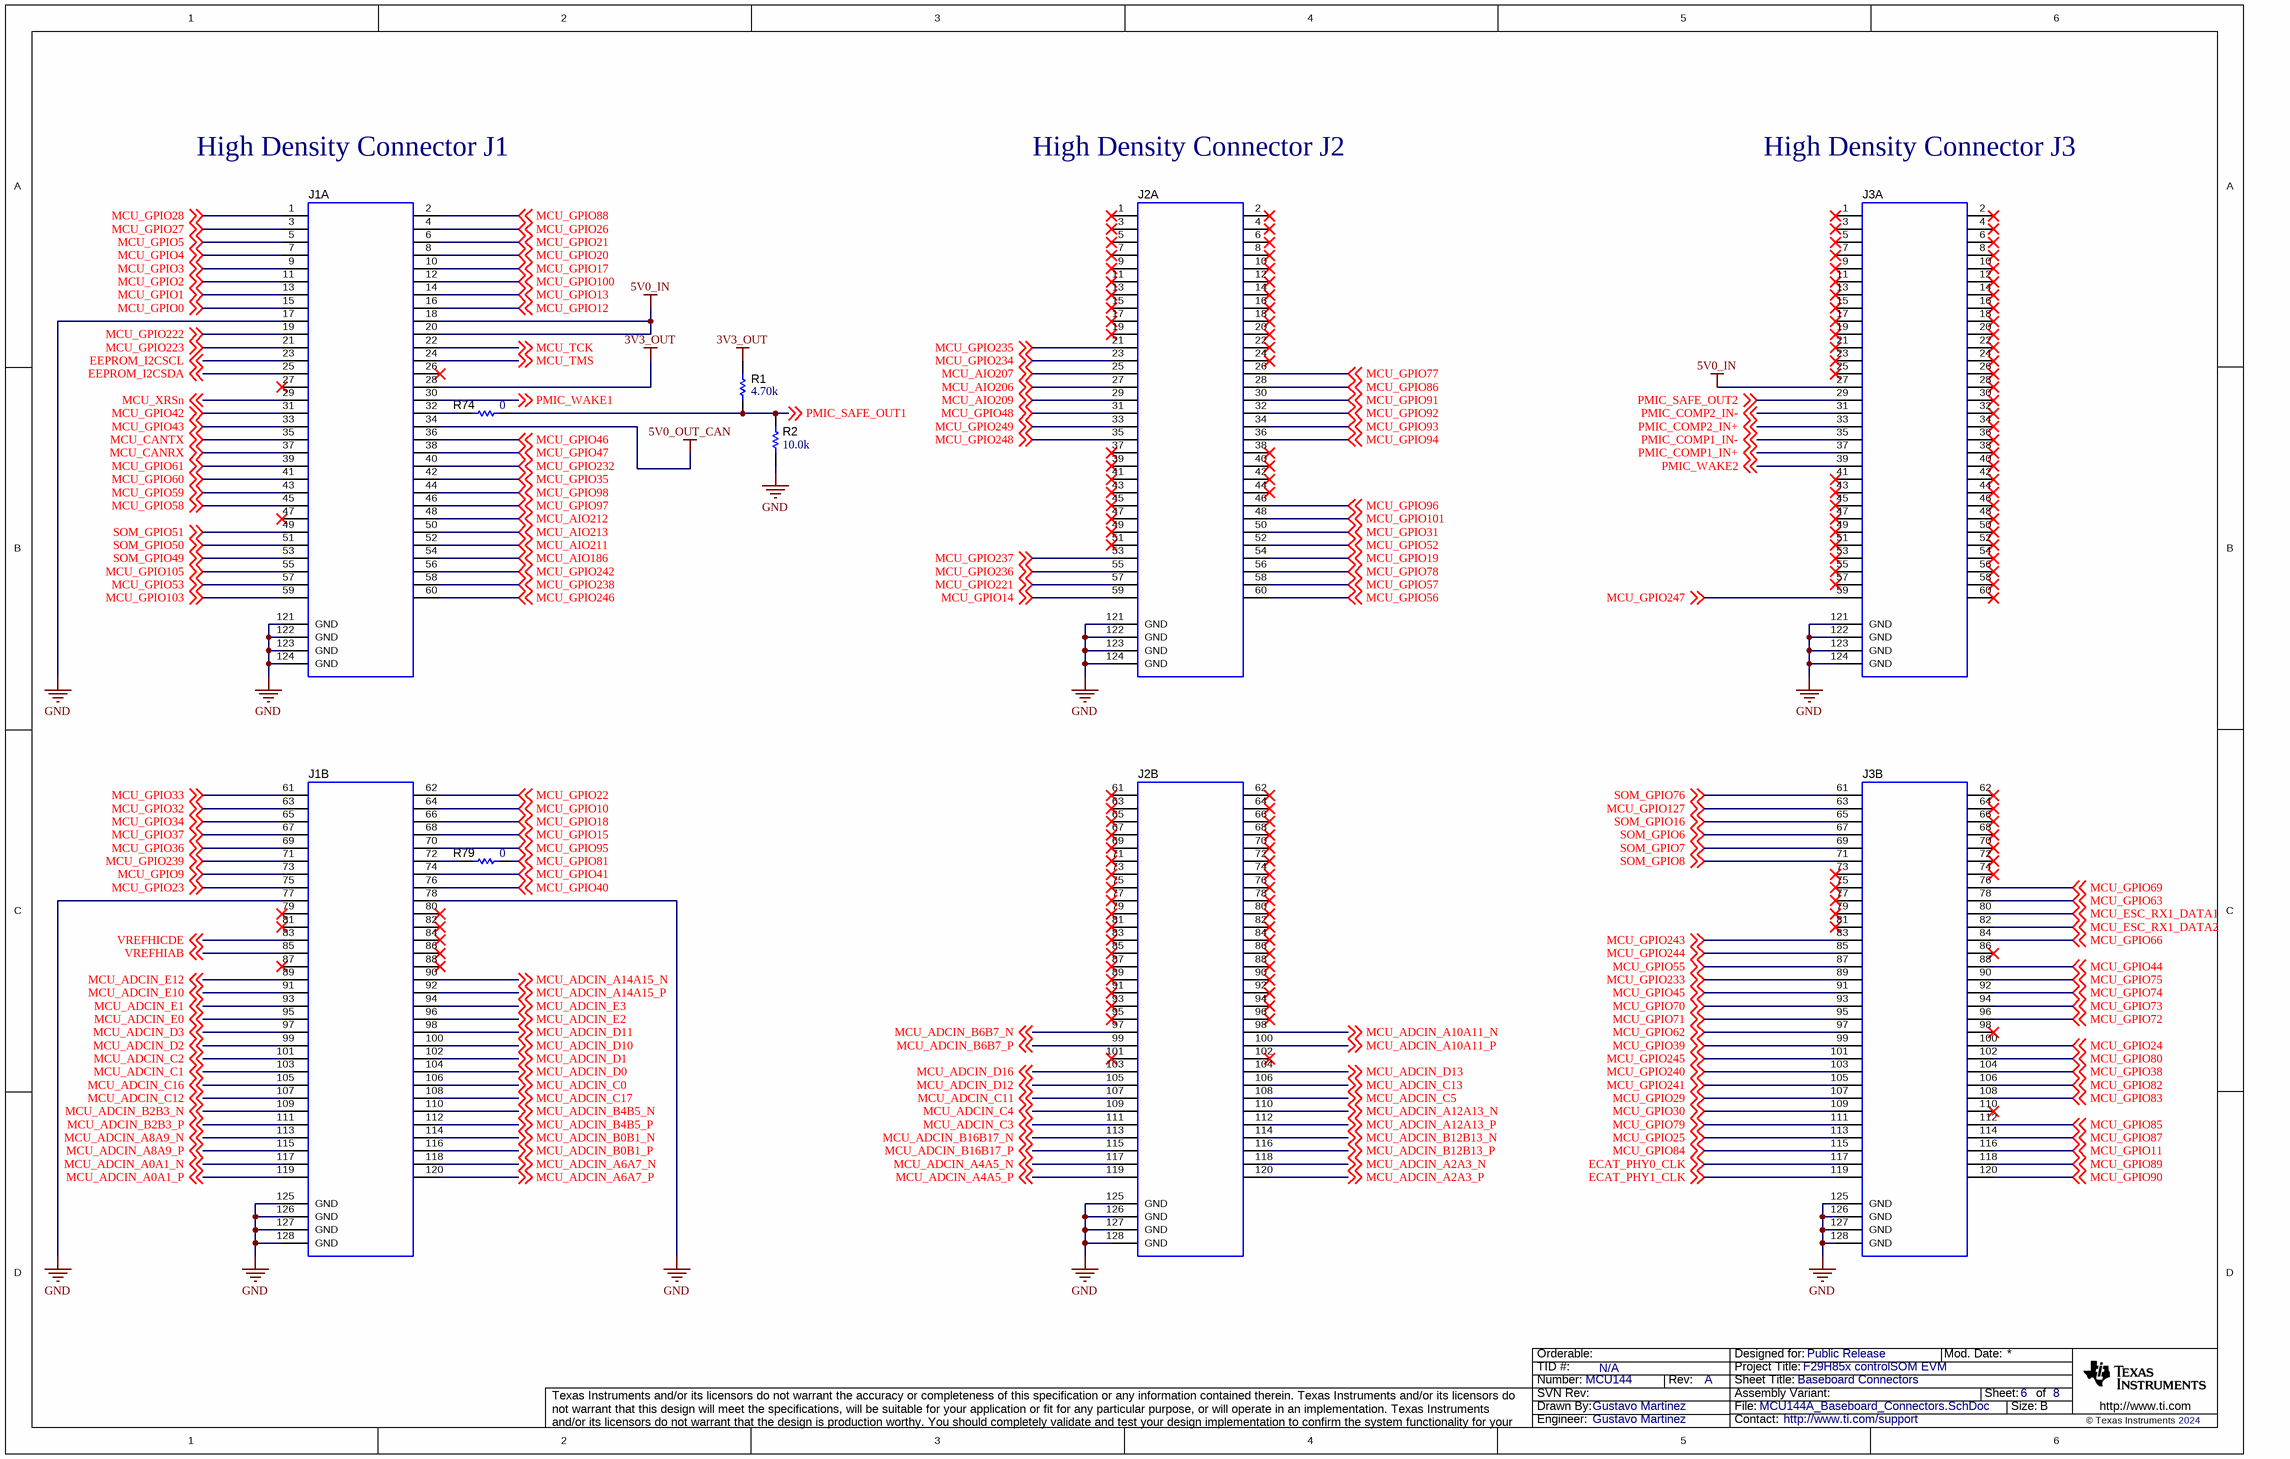
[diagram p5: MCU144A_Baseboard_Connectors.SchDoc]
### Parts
J1  QSH-060-01-L-D-A  [CONN_QSH-060-01-L-D-A]  (value not drawn)  (parts A,B of 2)
J2  QSH-060-01-L-D-A  [CONN_QSH-060-01-L-D-A]  (value not drawn)  (parts A,B of 2)
J3  QSH-060-01-L-D-A  [CONN_QSH-060-01-L-D-A]  (value not drawn)  (parts A,B of 2)
R1  value 4.70k  [0402]  (hidden comment: CRG0402F4K7)
R2  value 10.0k  [0402]  (hidden comment: AC0402FR-0710KL)
R74  ValueDisplayed: 0  [0402]  (hidden comment: CRCW04020000Z0ED)
R79  ValueDisplayed: 0  [0402]  (hidden comment: CRCW04020000Z0ED)

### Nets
3V3_OUT: J1.28 R1.2
5V0_IN: J1.18 J1.20 J3.27
5V0_OUT_CAN: J1.34
GND: J1.17 J1.77 J1.78 J1.121(GND) J1.122(GND) J1.123(GND) J1.124(GND) J1.125(GND) J1.126(GND) J1.127(GND) J1.128(GND) J2.121(GND) J2.122(GND) J2.123(GND) J2.124(GND) J2.125(GND) J2.126(GND) J2.127(GND) J2.128(GND) J3.121(GND) J3.122(GND) J3.123(GND) J3.124(GND) J3.125(GND) J3.126(GND) J3.127(GND) J3.128(GND) R2.1
ECAT_PHY0_CLK: J3.117 ; off-sheet ECAT_PHY0_CLK
ECAT_PHY1_CLK: J3.119 ; off-sheet ECAT_PHY1_CLK
EEPROM_I2CSCL: J1.23 ; off-sheet EEPROM_I2CSCL
EEPROM_I2CSDA: J1.25 ; off-sheet EEPROM_I2CSDA
MCU_ADCIN_A0A1_N: J1.117 ; off-sheet MCU_ADCIN_A0A1_N
MCU_ADCIN_A0A1_P: J1.119 ; off-sheet MCU_ADCIN_A0A1_P
MCU_ADCIN_A2A3_N: J2.118 ; off-sheet MCU_ADCIN_A2A3_N
MCU_ADCIN_A2A3_P: J2.120 ; off-sheet MCU_ADCIN_A2A3_P
MCU_ADCIN_A4A5_N: J2.117 ; off-sheet MCU_ADCIN_A4A5_N
MCU_ADCIN_A4A5_P: J2.119 ; off-sheet MCU_ADCIN_A4A5_P
MCU_ADCIN_A6A7_N: J1.118 ; off-sheet MCU_ADCIN_A6A7_N
MCU_ADCIN_A6A7_P: J1.120 ; off-sheet MCU_ADCIN_A6A7_P
MCU_ADCIN_A8A9_N: J1.113 ; off-sheet MCU_ADCIN_A8A9_N
MCU_ADCIN_A8A9_P: J1.115 ; off-sheet MCU_ADCIN_A8A9_P
MCU_ADCIN_A10A11_N: J2.98 ; off-sheet MCU_ADCIN_A10A11_N
MCU_ADCIN_A10A11_P: J2.100 ; off-sheet MCU_ADCIN_A10A11_P
MCU_ADCIN_A12A13_N: J2.110 ; off-sheet MCU_ADCIN_A12A13_N
MCU_ADCIN_A12A13_P: J2.112 ; off-sheet MCU_ADCIN_A12A13_P
MCU_ADCIN_A14A15_N: J1.90 ; off-sheet MCU_ADCIN_A14A15_N
MCU_ADCIN_A14A15_P: J1.92 ; off-sheet MCU_ADCIN_A14A15_P
MCU_ADCIN_B0B1_N: J1.114 ; off-sheet MCU_ADCIN_B0B1_N
MCU_ADCIN_B0B1_P: J1.116 ; off-sheet MCU_ADCIN_B0B1_P
MCU_ADCIN_B2B3_N: J1.109 ; off-sheet MCU_ADCIN_B2B3_N
MCU_ADCIN_B2B3_P: J1.111 ; off-sheet MCU_ADCIN_B2B3_P
MCU_ADCIN_B4B5_N: J1.110 ; off-sheet MCU_ADCIN_B4B5_N
MCU_ADCIN_B4B5_P: J1.112 ; off-sheet MCU_ADCIN_B4B5_P
MCU_ADCIN_B6B7_N: J2.97 ; off-sheet MCU_ADCIN_B6B7_N
MCU_ADCIN_B6B7_P: J2.99 ; off-sheet MCU_ADCIN_B6B7_P
MCU_ADCIN_B12B13_N: J2.114 ; off-sheet MCU_ADCIN_B12B13_N
MCU_ADCIN_B12B13_P: J2.116 ; off-sheet MCU_ADCIN_B12B13_P
MCU_ADCIN_B16B17_N: J2.113 ; off-sheet MCU_ADCIN_B16B17_N
MCU_ADCIN_B16B17_P: J2.115 ; off-sheet MCU_ADCIN_B16B17_P
MCU_ADCIN_C0: J1.106 ; off-sheet MCU_ADCIN_C0
MCU_ADCIN_C1: J1.103 ; off-sheet MCU_ADCIN_C1
MCU_ADCIN_C2: J1.101 ; off-sheet MCU_ADCIN_C2
MCU_ADCIN_C3: J2.111 ; off-sheet MCU_ADCIN_C3
MCU_ADCIN_C4: J2.109 ; off-sheet MCU_ADCIN_C4
MCU_ADCIN_C5: J2.108 ; off-sheet MCU_ADCIN_C5
MCU_ADCIN_C11: J2.107 ; off-sheet MCU_ADCIN_C11
MCU_ADCIN_C12: J1.107 ; off-sheet MCU_ADCIN_C12
MCU_ADCIN_C13: J2.106 ; off-sheet MCU_ADCIN_C13
MCU_ADCIN_C16: J1.105 ; off-sheet MCU_ADCIN_C16
MCU_ADCIN_C17: J1.108 ; off-sheet MCU_ADCIN_C17
MCU_ADCIN_D0: J1.104 ; off-sheet MCU_ADCIN_D0
MCU_ADCIN_D1: J1.102 ; off-sheet MCU_ADCIN_D1
MCU_ADCIN_D2: J1.99 ; off-sheet MCU_ADCIN_D2
MCU_ADCIN_D3: J1.97 ; off-sheet MCU_ADCIN_D3
MCU_ADCIN_D10: J1.100 ; off-sheet MCU_ADCIN_D10
MCU_ADCIN_D11: J1.98 ; off-sheet MCU_ADCIN_D11
MCU_ADCIN_D12: J2.105 ; off-sheet MCU_ADCIN_D12
MCU_ADCIN_D13: J2.104 ; off-sheet MCU_ADCIN_D13
MCU_ADCIN_D16: J2.103 ; off-sheet MCU_ADCIN_D16
MCU_ADCIN_E0: J1.95 ; off-sheet MCU_ADCIN_E0
MCU_ADCIN_E1: J1.93 ; off-sheet MCU_ADCIN_E1
MCU_ADCIN_E2: J1.96 ; off-sheet MCU_ADCIN_E2
MCU_ADCIN_E3: J1.94 ; off-sheet MCU_ADCIN_E3
MCU_ADCIN_E10: J1.91 ; off-sheet MCU_ADCIN_E10
MCU_ADCIN_E12: J1.89 ; off-sheet MCU_ADCIN_E12
MCU_AIO186: J1.54 ; off-sheet MCU_AIO186
MCU_AIO206: J2.27 ; off-sheet MCU_AIO206
MCU_AIO207: J2.25 ; off-sheet MCU_AIO207
MCU_AIO209: J2.29 ; off-sheet MCU_AIO209
MCU_AIO211: J1.52 ; off-sheet MCU_AIO211
MCU_AIO212: J1.48 ; off-sheet MCU_AIO212
MCU_AIO213: J1.50 ; off-sheet MCU_AIO213
MCU_CANRX: J1.37 ; off-sheet MCU_CANRX
MCU_CANTX: J1.35 ; off-sheet MCU_CANTX
MCU_ESC_RX1_DATA1: J3.80 ; off-sheet MCU_ESC_RX1_DATA1
MCU_ESC_RX1_DATA2: J3.82 ; off-sheet MCU_ESC_RX1_DATA2
MCU_GPIO0: J1.15 ; off-sheet MCU_GPIO0
MCU_GPIO1: J1.13 ; off-sheet MCU_GPIO1
MCU_GPIO2: J1.11 ; off-sheet MCU_GPIO2
MCU_GPIO3: J1.9 ; off-sheet MCU_GPIO3
MCU_GPIO4: J1.7 ; off-sheet MCU_GPIO4
MCU_GPIO5: J1.5 ; off-sheet MCU_GPIO5
MCU_GPIO9: J1.73 ; off-sheet MCU_GPIO9
MCU_GPIO10: J1.64 ; off-sheet MCU_GPIO10
MCU_GPIO11: J3.116 ; off-sheet MCU_GPIO11
MCU_GPIO12: J1.16 ; off-sheet MCU_GPIO12
MCU_GPIO13: J1.14 ; off-sheet MCU_GPIO13
MCU_GPIO14: J2.59 ; off-sheet MCU_GPIO14
MCU_GPIO15: J1.68 ; off-sheet MCU_GPIO15
MCU_GPIO17: J1.10 ; off-sheet MCU_GPIO17
MCU_GPIO18: J1.66 ; off-sheet MCU_GPIO18
MCU_GPIO19: J2.54 ; off-sheet MCU_GPIO19
MCU_GPIO20: J1.8 ; off-sheet MCU_GPIO20
MCU_GPIO21: J1.6 ; off-sheet MCU_GPIO21
MCU_GPIO22: J1.62 ; off-sheet MCU_GPIO22
MCU_GPIO23: J1.75 ; off-sheet MCU_GPIO23
MCU_GPIO24: J3.100 ; off-sheet MCU_GPIO24
MCU_GPIO25: J3.113 ; off-sheet MCU_GPIO25
MCU_GPIO26: J1.4 ; off-sheet MCU_GPIO26
MCU_GPIO27: J1.3 ; off-sheet MCU_GPIO27
MCU_GPIO28: J1.1 ; off-sheet MCU_GPIO28
MCU_GPIO29: J3.107 ; off-sheet MCU_GPIO29
MCU_GPIO30: J3.109 ; off-sheet MCU_GPIO30
MCU_GPIO31: J2.50 ; off-sheet MCU_GPIO31
MCU_GPIO32: J1.63 ; off-sheet MCU_GPIO32
MCU_GPIO33: J1.61 ; off-sheet MCU_GPIO33
MCU_GPIO34: J1.65 ; off-sheet MCU_GPIO34
MCU_GPIO35: J1.42 ; off-sheet MCU_GPIO35
MCU_GPIO36: J1.69 ; off-sheet MCU_GPIO36
MCU_GPIO37: J1.67 ; off-sheet MCU_GPIO37
MCU_GPIO38: J3.104 ; off-sheet MCU_GPIO38
MCU_GPIO39: J3.99 ; off-sheet MCU_GPIO39
MCU_GPIO40: J1.76 ; off-sheet MCU_GPIO40
MCU_GPIO41: J1.74 ; off-sheet MCU_GPIO41
MCU_GPIO42: J1.31 ; off-sheet MCU_GPIO42
MCU_GPIO43: J1.33 ; off-sheet MCU_GPIO43
MCU_GPIO44: J3.88 ; off-sheet MCU_GPIO44
MCU_GPIO45: J3.91 ; off-sheet MCU_GPIO45
MCU_GPIO46: J1.36 ; off-sheet MCU_GPIO46
MCU_GPIO47: J1.38 ; off-sheet MCU_GPIO47
MCU_GPIO48: J2.31 ; off-sheet MCU_GPIO48
MCU_GPIO52: J2.52 ; off-sheet MCU_GPIO52
MCU_GPIO53: J1.57 ; off-sheet MCU_GPIO53
MCU_GPIO55: J3.87 ; off-sheet MCU_GPIO55
MCU_GPIO56: J2.60 ; off-sheet MCU_GPIO56
MCU_GPIO57: J2.58 ; off-sheet MCU_GPIO57
MCU_GPIO58: J1.45 ; off-sheet MCU_GPIO58
MCU_GPIO59: J1.43 ; off-sheet MCU_GPIO59
MCU_GPIO60: J1.41 ; off-sheet MCU_GPIO60
MCU_GPIO61: J1.39 ; off-sheet MCU_GPIO61
MCU_GPIO62: J3.97 ; off-sheet MCU_GPIO62
MCU_GPIO63: J3.78 ; off-sheet MCU_GPIO63
MCU_GPIO66: J3.84 ; off-sheet MCU_GPIO66
MCU_GPIO69: J3.76 ; off-sheet MCU_GPIO69
MCU_GPIO70: J3.93 ; off-sheet MCU_GPIO70
MCU_GPIO71: J3.95 ; off-sheet MCU_GPIO71
MCU_GPIO72: J3.96 ; off-sheet MCU_GPIO72
MCU_GPIO73: J3.94 ; off-sheet MCU_GPIO73
MCU_GPIO74: J3.92 ; off-sheet MCU_GPIO74
MCU_GPIO75: J3.90 ; off-sheet MCU_GPIO75
MCU_GPIO77: J2.26 ; off-sheet MCU_GPIO77
MCU_GPIO78: J2.56 ; off-sheet MCU_GPIO78
MCU_GPIO79: J3.111 ; off-sheet MCU_GPIO79
MCU_GPIO80: J3.102 ; off-sheet MCU_GPIO80
MCU_GPIO81: R79.2 ; off-sheet MCU_GPIO81
MCU_GPIO82: J3.106 ; off-sheet MCU_GPIO82
MCU_GPIO83: J3.108 ; off-sheet MCU_GPIO83
MCU_GPIO84: J3.115 ; off-sheet MCU_GPIO84
MCU_GPIO85: J3.112 ; off-sheet MCU_GPIO85
MCU_GPIO86: J2.28 ; off-sheet MCU_GPIO86
MCU_GPIO87: J3.114 ; off-sheet MCU_GPIO87
MCU_GPIO88: J1.2 ; off-sheet MCU_GPIO88
MCU_GPIO89: J3.118 ; off-sheet MCU_GPIO89
MCU_GPIO90: J3.120 ; off-sheet MCU_GPIO90
MCU_GPIO91: J2.30 ; off-sheet MCU_GPIO91
MCU_GPIO92: J2.32 ; off-sheet MCU_GPIO92
MCU_GPIO93: J2.34 ; off-sheet MCU_GPIO93
MCU_GPIO94: J2.36 ; off-sheet MCU_GPIO94
MCU_GPIO95: J1.70 ; off-sheet MCU_GPIO95
MCU_GPIO96: J2.46 ; off-sheet MCU_GPIO96
MCU_GPIO97: J1.46 ; off-sheet MCU_GPIO97
MCU_GPIO98: J1.44 ; off-sheet MCU_GPIO98
MCU_GPIO100: J1.12 ; off-sheet MCU_GPIO100
MCU_GPIO101: J2.48 ; off-sheet MCU_GPIO101
MCU_GPIO103: J1.59 ; off-sheet MCU_GPIO103
MCU_GPIO105: J1.55 ; off-sheet MCU_GPIO105
MCU_GPIO127: J3.63 ; off-sheet MCU_GPIO127
MCU_GPIO221: J2.57 ; off-sheet MCU_GPIO221
MCU_GPIO222: J1.19 ; off-sheet MCU_GPIO222
MCU_GPIO223: J1.21 ; off-sheet MCU_GPIO223
MCU_GPIO232: J1.40 ; off-sheet MCU_GPIO232
MCU_GPIO233: J3.89 ; off-sheet MCU_GPIO233
MCU_GPIO234: J2.23 ; off-sheet MCU_GPIO234
MCU_GPIO235: J2.21 ; off-sheet MCU_GPIO235
MCU_GPIO236: J2.55 ; off-sheet MCU_GPIO236
MCU_GPIO237: J2.53 ; off-sheet MCU_GPIO237
MCU_GPIO238: J1.58 ; off-sheet MCU_GPIO238
MCU_GPIO239: J1.71 ; off-sheet MCU_GPIO239
MCU_GPIO240: J3.103 ; off-sheet MCU_GPIO240
MCU_GPIO241: J3.105 ; off-sheet MCU_GPIO241
MCU_GPIO242: J1.56 ; off-sheet MCU_GPIO242
MCU_GPIO243: J3.83 ; off-sheet MCU_GPIO243
MCU_GPIO244: J3.85 ; off-sheet MCU_GPIO244
MCU_GPIO245: J3.101 ; off-sheet MCU_GPIO245
MCU_GPIO246: J1.60 ; off-sheet MCU_GPIO246
MCU_GPIO247: J3.59 ; off-sheet MCU_GPIO247
MCU_GPIO248: J2.35 ; off-sheet MCU_GPIO248
MCU_GPIO249: J2.33 ; off-sheet MCU_GPIO249
MCU_TCK: J1.22 ; off-sheet MCU_TCK
MCU_TMS: J1.24 ; off-sheet MCU_TMS
MCU_XRSn: J1.29 ; off-sheet MCU_XRSn
PMIC_COMP1_IN+: J3.37 ; off-sheet PMIC_COMP1_IN+
PMIC_COMP1_IN-: J3.35 ; off-sheet PMIC_COMP1_IN-
PMIC_COMP2_IN+: J3.33 ; off-sheet PMIC_COMP2_IN+
PMIC_COMP2_IN-: J3.31 ; off-sheet PMIC_COMP2_IN-
PMIC_SAFE_OUT1: R1.1 R2.2 R74.2 ; off-sheet PMIC_SAFE_OUT1
PMIC_SAFE_OUT2: J3.29 ; off-sheet PMIC_SAFE_OUT2
PMIC_WAKE1: J1.30 ; off-sheet PMIC_WAKE1
PMIC_WAKE2: J3.39 ; off-sheet PMIC_WAKE2
SOM_GPIO6: J3.67 ; off-sheet SOM_GPIO6
SOM_GPIO7: J3.69 ; off-sheet SOM_GPIO7
SOM_GPIO8: J3.71 ; off-sheet SOM_GPIO8
SOM_GPIO16: J3.65 ; off-sheet SOM_GPIO16
SOM_GPIO49: J1.53 ; off-sheet SOM_GPIO49
SOM_GPIO50: J1.51 ; off-sheet SOM_GPIO50
SOM_GPIO51: J1.49 ; off-sheet SOM_GPIO51
SOM_GPIO76: J3.61 ; off-sheet SOM_GPIO76
VREFHIAB: J1.85 ; off-sheet VREFHIAB
VREFHICDE: J1.83 ; off-sheet VREFHICDE
NetJ1_32: J1.32 R74.1
NetJ1_72: J1.72 R79.1

Not connected (* = marked no-connect by the designer): J1 26* 27* 47* 79* 80* 81* 82* 84* 86* 87* 88*; J2 1* 2* 3* 4* 5* 6* 7* 8* 9* 10* 11* 12* 13* 14* 15* 16* 17* 18* 19* 20* 22* 24* 37* 38* 39* 40* 41* 42* 43* 44* 45* 47* 49* 51* 61* 62* 63* 64* 65* 66* 67* 68* 69* 70* 71* 72* 73* 74* 75* 76* 77* 78* 79* 80* 81* 82* 83* 84* 85* 86* 87* 88* 89* 90* 91* 92* 93* 94* 95* 96* 101* 102*; J3 1* 2* 3* 4* 5* 6* 7* 8* 9* 10* 11* 12* 13* 14* 15* 16* 17* 18* 19* 20* 21* 22* 23* 24* 25* 26* 28* 30* 32* 34* 36* 38* 40* 41* 42* 43* 44* 45* 46* 47* 48* 49* 50* 51* 52* 53* 54* 55* 56* 57* 58* 60* 62* 64* 66* 68* 70* 72* 73* 74* 75* 77* 79* 81* 86* 98* 110*

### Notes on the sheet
- High Density Connector J1
- High Density Connector J2
- High Density Connector J3

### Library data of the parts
J1-J3 = CMP-0055973-1: Connector,  0.5mm, 60x2, SMT; Manufacturer: Samtec; CT: FALSE
R1 = CMP-0026631-1: as R10 on sheet MCU144A_SOM_Power
R2 = CMP-0077731-1: as R11 on sheet MCU144A_SOM_Power
R74 R79 = CMP-0026822-3: as R7 on sheet MCU144A_SOM_Power

## Sheet MCU144A_Emulation_Connectors.SchDoc: Emulation Connectors
size 431 x 279 mm; DrawnBy: Gustavo Martinez; SheetNumber: 7; SheetTotal: 8

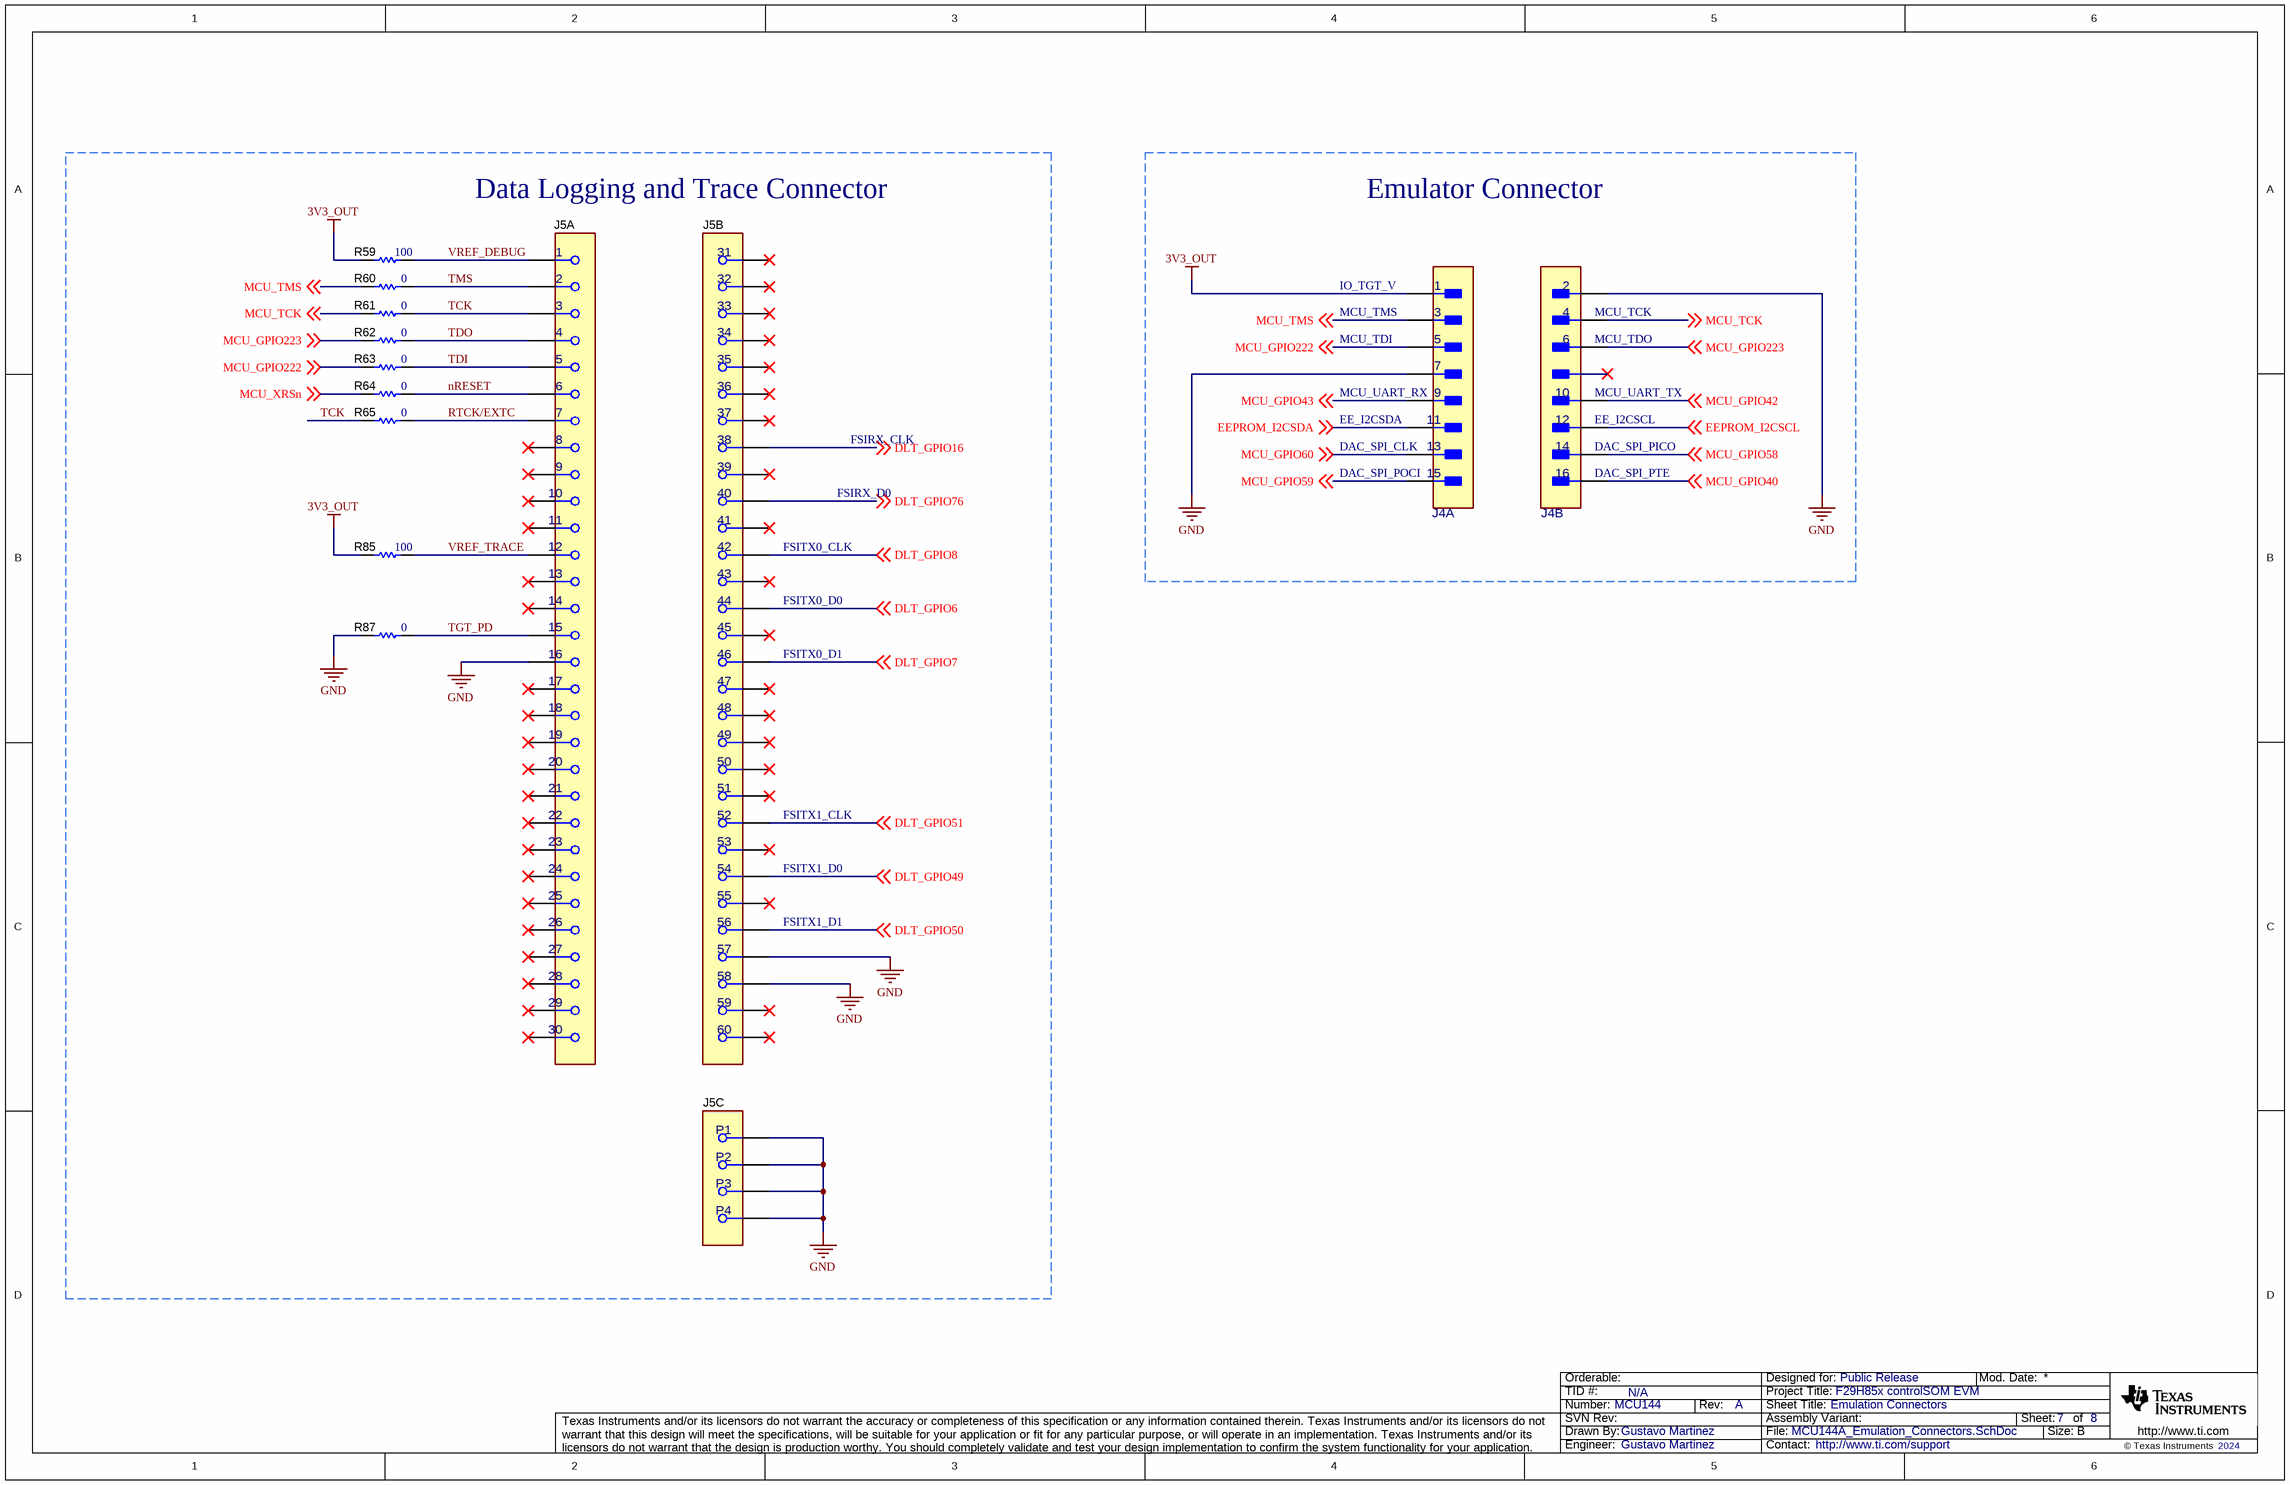
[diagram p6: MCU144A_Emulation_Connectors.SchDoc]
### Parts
J4  TSM-108-01-L-DV-008-P-TR  [FP-TSM-108-01-L-DV-008-P-TR_HDR15-MFG]  (value not drawn)  (parts A,B of 2)
J5  QSH-030-01-L-D-A  [FP-QSH-030-01-L-D-A_CONN_60-MFG]  (value not drawn)  (parts A,B,C of 3)
R59  ValueDisplayed: 100  [0402]  (hidden comment: CRCW0402100RFKED)
R60  ValueDisplayed: 0  [0402]  (hidden comment: CRCW04020000Z0ED)
R61  ValueDisplayed: 0  [0402]  (hidden comment: CRCW04020000Z0ED)
R62  ValueDisplayed: 0  [0402]  (hidden comment: CRCW04020000Z0ED)
R63  ValueDisplayed: 0  [0402]  (hidden comment: CRCW04020000Z0ED)
R64  ValueDisplayed: 0  [0402]  (hidden comment: CRCW04020000Z0ED)
R65  ValueDisplayed: 0  [0402]  (hidden comment: CRCW04020000Z0ED)
R85  ValueDisplayed: 100  [0402]  (hidden comment: CRCW0402100RFKED)
R87  ValueDisplayed: 0  [0402]  (hidden comment: CRCW04020000Z0ED)

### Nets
3V3_OUT: J4.1 R59.1 R85.1
GND: J4.2 J4.7 J5.16 J5.57 J5.58 J5.P1 J5.P2 J5.P3 J5.P4 R87.1
DLT_GPIO6: J5.44 ; off-sheet DLT_GPIO6
DLT_GPIO7: J5.46 ; off-sheet DLT_GPIO7
DLT_GPIO8: J5.42 ; off-sheet DLT_GPIO8
DLT_GPIO16: J5.38 ; off-sheet DLT_GPIO16
DLT_GPIO49: J5.54 ; off-sheet DLT_GPIO49
DLT_GPIO50: J5.56 ; off-sheet DLT_GPIO50
DLT_GPIO51: J5.52 ; off-sheet DLT_GPIO51
DLT_GPIO76: J5.40 ; off-sheet DLT_GPIO76
EEPROM_I2CSCL: J4.12 ; off-sheet EEPROM_I2CSCL
EEPROM_I2CSDA: J4.11 ; off-sheet EEPROM_I2CSDA
MCU_GPIO40: J4.16 ; off-sheet MCU_GPIO40
MCU_GPIO42: J4.10 ; off-sheet MCU_GPIO42
MCU_GPIO43: J4.9 ; off-sheet MCU_GPIO43
MCU_GPIO58: J4.14 ; off-sheet MCU_GPIO58
MCU_GPIO59: J4.15 ; off-sheet MCU_GPIO59
MCU_GPIO60: J4.13 ; off-sheet MCU_GPIO60
MCU_GPIO222: J4.5 R63.1 ; off-sheet MCU_GPIO222
MCU_GPIO223: J4.6 R62.1 ; off-sheet MCU_GPIO223
MCU_TCK: J4.4 R61.1 ; off-sheet MCU_TCK
MCU_TMS: J4.3 R60.1 ; off-sheet MCU_TMS
MCU_XRSn: R64.1 ; off-sheet MCU_XRSn
nRESET: J5.6 R64.2
RTCK/EXTC: J5.7 R65.2
TCK: J5.3 R61.2 R65.1
TDI: J5.5 R63.2
TDO: J5.4 R62.2
TGT_PD: J5.15 R87.2
TMS: J5.2 R60.2
VREF_DEBUG: J5.1 R59.2
VREF_TRACE: J5.12 R85.2

Not connected (* = marked no-connect by the designer): J5 8* 9* 10* 11* 13* 14* 17* 18* 19* 20* 21* 22* 23* 24* 25* 26* 27* 28* 29* 30* 31* 32* 33* 34* 35* 36* 37* 39* 41* 43* 45* 47* 48* 49* 50* 51* 53* 55* 59* 60*

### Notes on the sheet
- Data Logging and Trace Connector
- Emulator Connector
- (near J4) IO_TGT_V
- (near J4) MCU_TDI
- (near J4) MCU_TMS
- (near J4) MCU_TCK
- (near J4) MCU_TDO
- (near J4) MCU_UART_RX
- (near J4) EE_I2CSDA
- (near J4) EE_I2CSCL
- (near J4) MCU_UART_TX
- (near J5) FSIRX_D0
- (near J5) FSIRX_CLK
- (near J4) DAC_SPI_POCI
- (near J4) DAC_SPI_CLK
- (near J4) DAC_SPI_PICO
- (near J4) DAC_SPI_PTE
- (near J5) FSITX0_CLK
- (near J5) FSITX0_D0
- (near J5) FSITX0_D1
- (near J5) FSITX1_CLK
- (near J5) FSITX1_D0
- (near J5) FSITX1_D1

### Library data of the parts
J4 = CMP-0121706-1: Conn Unshrouded HDR 16 POS 2.54mm Solder ST SMT; Manufacturer: Samtec; ContactFinish: Gold,Nickel; Row_Count: 2; AEC Qualified: No; Conn Gender: Male; Conn Orientation: Vertical; SizeZ_mm: 10.16mm; Standoff Height: 1.02mm
J5 = CMP-0088387-1: CONN RCPT HI-SPD .5MM 60POS DL; Manufacturer: Samtec; Voltage_V: 175V; AEC Qualified: No; Current_A: 25A; DUT-Pitch_mm: 0.5mm; Standoff Height: 0.407mm; Row_Count: 2; Conn Gender: Female; SizeZ_mm: 3.327mm; ContactFinish: Gold,Nickel; Conn Orientation: Vertical; Is Female: yes
R59 R85 = CMP-0025951-3: RES, 100, 1%, 0.063 W, AEC-Q200 Grade 0, 0402; Manufacturer: Vishay-Dale; Power_W: 63mW; TempCo: 100 ppm/C; Value_Code: 100R; Value: 100; EIA_Code: E96; SizeX_mm: 1; SizeY_mm: 0.5; SizeZ_mm: 0.6; Value2: 0.063W; AEC Qualified: Y; VDC_V: 50V; AEC Category: Q200; AEC Grade: 0
R60-R65 R87 = CMP-0026822-3: RES, 0, 5%, 0.063 W, AEC-Q200 Grade 0, 0402; Manufacturer: Vishay-Dale; Power_W: 63mW; TempCo: 200 ppm/C; Value_Code: 0000; Value: 0; EIA_Code: E24; SizeX_mm: 1; SizeY_mm: 0.5; SizeZ_mm: 0.6; Value2: 0.063W; AEC Qualified: Y; AEC Category: Q200; VDC_V: 50V

## Sheet MCU144A_EVM_Hardware.SchDoc: EVM Hardware
size 431 x 279 mm; Date: Not shown in title block; ApprovedBy: Not shown in title block; CheckedBy: Not shown in title block; Author: Not shown in title block; CompanyName: Not shown in title block; DrawnBy: Gustavo Martinez; Engineer: Not shown in title block; Organization: Not shown in title block; Address1: Not shown in title block; Address2: Not shown in title block; Address3: Not shown in title block; Address4: Not shown in title block; DocumentNumber: 11; Revision: Use project parameter SCH_Rev; SheetNumber: 8; SheetTotal: 8; PageSetup: Record=PageOptions¦CenterHorizontal=True¦CenterVertical=True¦PrintScale=1.00¦XCorrection=1.00¦YCorrection=1.00¦PrintKind=0¦BorderSize=5000000¦LeftOffset=0¦BottomOffset=0¦Orientation=2¦PaperLength=1000¦PaperWidth=1000¦Scale=100¦PaperSource=15¦PrintQuality=600¦MediaType=1¦DitherType=10¦PaperKind=Letter¦PrintScaleMode=1

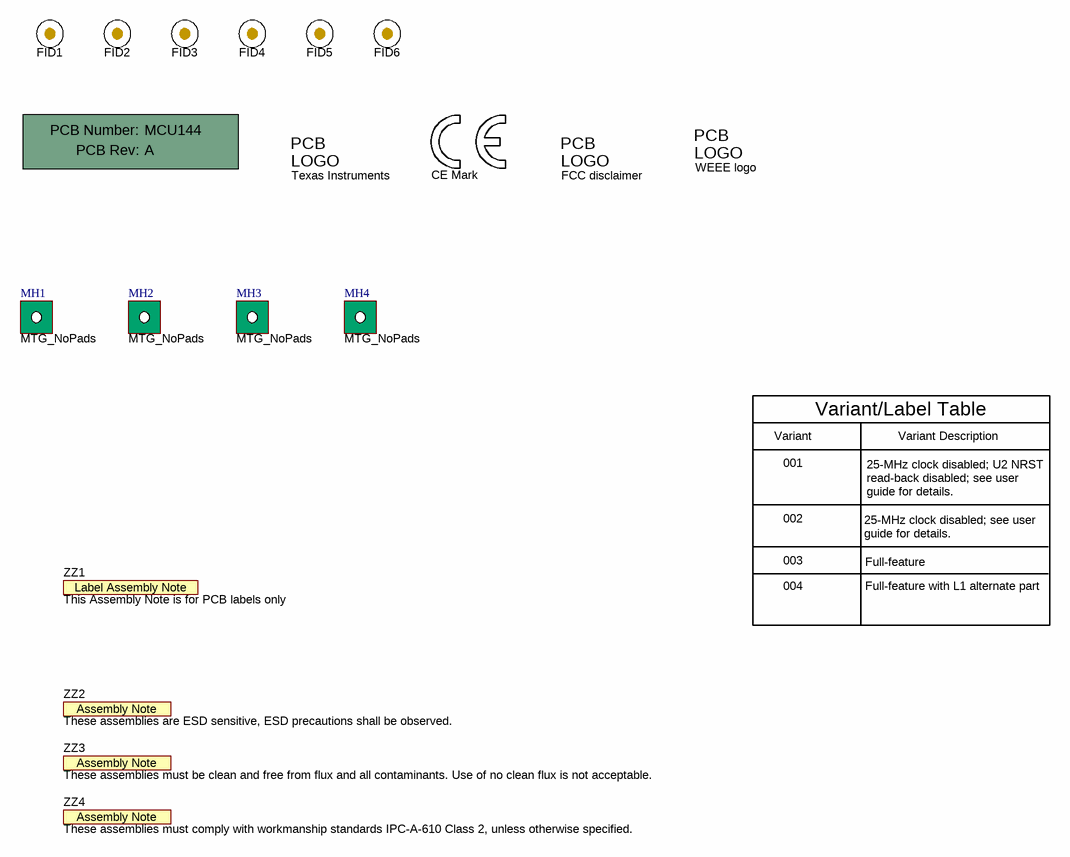
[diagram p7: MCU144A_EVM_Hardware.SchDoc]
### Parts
!PCB1  Printed Circuit Board  (value not drawn)  (mechanical)
FID1  Fiducial  [Fiducial10-20]  (value not drawn)  (no BOM)
FID2  Fiducial  [Fiducial10-20]  (value not drawn)  (no BOM)
FID3  Fiducial  [Fiducial10-20]  (value not drawn)  (no BOM)
FID4  Fiducial  [Fiducial10-20]  (value not drawn)  (no BOM)
FID5  Fiducial  [Fiducial10-20]  (value not drawn)  (no BOM)
FID6  Fiducial  [Fiducial10-20]  (value not drawn)  (no BOM)
Logo1  CE Mark  [CE_Mark_5mm]  (no BOM)
Logo2  Texas Instruments  [TI_Stacked_Overlay_Small]  (no BOM)
Logo3  FCC disclaimer  [FCC_disclaimer]  (no BOM)
Logo4  WEEE logo  [WEEE_Minimum]  (no BOM)
MH1  MTG_NoPads  [MTG_159mil]  (no BOM)
MH2  MTG_NoPads  [MTG_159mil]  (no BOM)
MH3  MTG_NoPads  [MTG_159mil]  (no BOM)
MH4  MTG_NoPads  [MTG_159mil]  (no BOM)
ZZ1  This Assembly Note is for PCB labels only  [AssemblyNoteLabel]  (no BOM)
ZZ2  These assemblies are ESD sensitive, ESD precautions shall be observed.  [AssemblyNote]  (no BOM)
ZZ3  These assemblies must be clean and free from flux and all contaminants. Use of no clean flux is not acceptable.  [AssemblyNote]  (no BOM)
ZZ4  These assemblies must comply with workmanship standards IPC-A-610 Class 2, unless otherwise specified.  [AssemblyNote]  (no BOM)

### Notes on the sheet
- Variant
- Variant/Label Table
- Variant Description
- 001
- 25-MHz clock disabled; U2 NRST read-back disabled; see user guide for details.
- 002
- 003
- 25-MHz clock disabled; see user guide for details.
- 004
- Full-feature
- Full-feature with L1 alternate part

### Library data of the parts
!PCB1 = CMP-0003618-2: Manufacturer: Any; PartNumber: MCU144
FID1-FID6 = CMP-0077181-1: Fiducial mark.  There is nothing to buy or mount.
Logo1 = CMP-0074844-1: SymbolCreator: a0412235
Logo2 = CMP-0074838-1: Texas Instrument Corporate Signature; SymbolCreator: a0412235; Lib Reference: TI_Logo; Library Reference: Logo
Logo3 = CMP-0074847-1: FCC_disclaimer
Logo4 = CMP-0074769-3: Manufacturer: Texas Instruments; AEC Category: Q200; CompType: IC
MH1-MH4 = CMP-0078424-2: PCB Mounting Hole, No Pad; Manufacturer: Any; Key: Mounting Hole (non-standard) No Pad
ZZ1 = CMP-0003616-3
ZZ2 = CMP-0077236-1
ZZ3 = CMP-0077237-1
ZZ4 = CMP-0077238-1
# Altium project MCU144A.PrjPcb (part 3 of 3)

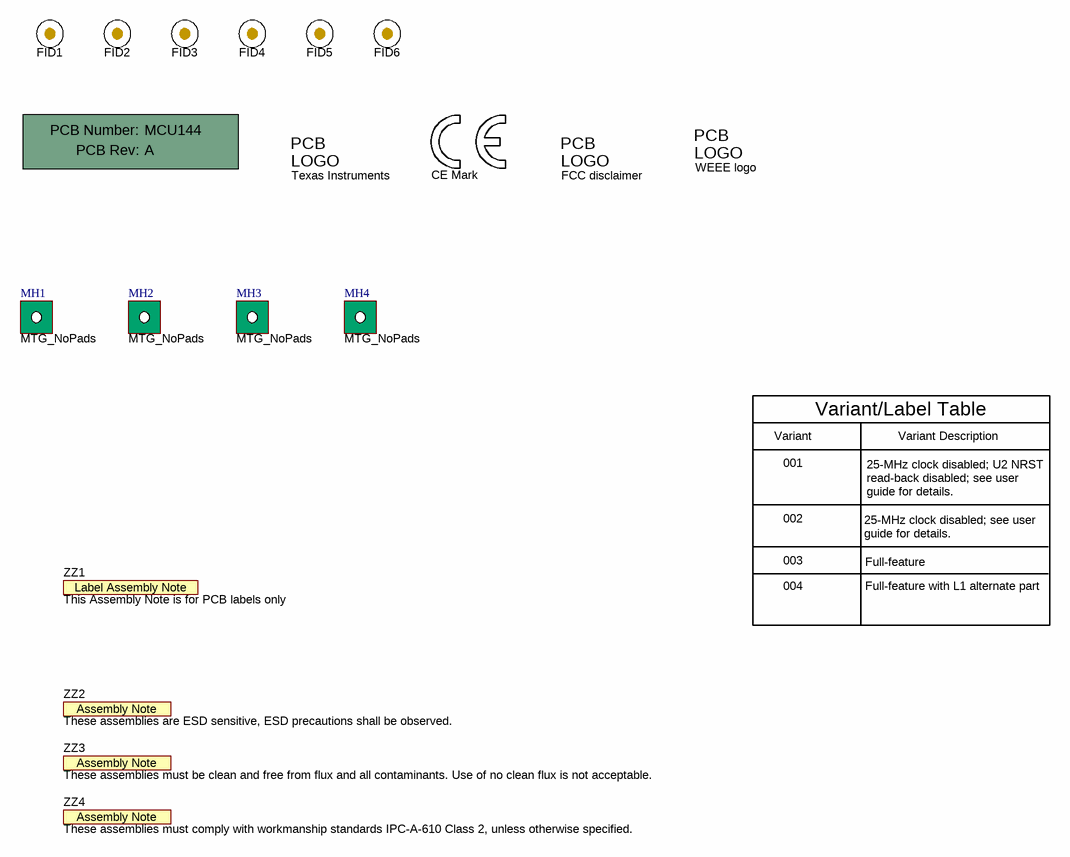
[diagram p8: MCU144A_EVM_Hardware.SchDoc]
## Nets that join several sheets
3V3_OUT: MCU144A_GPIO_Power (5 pins), MCU144A_Clock_Reset_Boot (17 pins), MCU144A_SOM_Power (8 pins), MCU144A_Baseboard_Connectors (J1.28 R1.2), MCU144A_Emulation_Connectors (J4.1 R59.1 R85.1)
5V0_IN: MCU144A_SOM_Power (8 pins), MCU144A_Baseboard_Connectors (J1.18 J1.20 J3.27)
5V0_OUT_CAN: MCU144A_GPIO_Power (R3.2 R23.2 R24.2), MCU144A_SOM_Power (C53.2 L6.2 TP17.1), MCU144A_Baseboard_Connectors (J1.34)
+1V25: MCU144A_GPIO_Power (C1.2 L1.1), MCU144A_SOM_Power (5 pins)
GND: MCU144A_GPIO_Power (65 pins), MCU144A_ADC (14 pins), MCU144A_Clock_Reset_Boot (18 pins), MCU144A_SOM_Power (66 pins), MCU144A_Baseboard_Connectors (28 pins), MCU144A_Emulation_Connectors (10 pins)
VDDA_3V3: MCU144A_GPIO_Power (7 pins), MCU144A_ADC (5 pins)
DLT_GPIO6: MCU144A_GPIO_Power (R91.1), MCU144A_Emulation_Connectors (J5.44)
DLT_GPIO7: MCU144A_GPIO_Power (R96.1), MCU144A_Emulation_Connectors (J5.46)
DLT_GPIO8: MCU144A_GPIO_Power (R83.1), MCU144A_Emulation_Connectors (J5.42)
DLT_GPIO16: MCU144A_GPIO_Power (R84.1), MCU144A_Emulation_Connectors (J5.38)
DLT_GPIO49: MCU144A_GPIO_Power (R90.1), MCU144A_Emulation_Connectors (J5.54)
DLT_GPIO50: MCU144A_GPIO_Power (R95.1), MCU144A_Emulation_Connectors (J5.56)
DLT_GPIO51: MCU144A_GPIO_Power (R82.1), MCU144A_Emulation_Connectors (J5.52)
DLT_GPIO76: MCU144A_GPIO_Power (R92.1), MCU144A_Emulation_Connectors (J5.40)
ECAT_PHY0_CLK: MCU144A_Clock_Reset_Boot (R31.1 R32.1), MCU144A_Baseboard_Connectors (J3.117)
ECAT_PHY1_CLK: MCU144A_Clock_Reset_Boot (R35.1 R97.1), MCU144A_Baseboard_Connectors (J3.119)
EEPROM_I2CSCL: MCU144A_Clock_Reset_Boot (R49.1 U6.6), MCU144A_Baseboard_Connectors (J1.23), MCU144A_Emulation_Connectors (J4.12)
EEPROM_I2CSDA: MCU144A_Clock_Reset_Boot (R50.1 U6.5), MCU144A_Baseboard_Connectors (J1.25), MCU144A_Emulation_Connectors (J4.11)
EXT_VMON2: MCU144A_ADC (R56.2 S3.2 U1.N2), MCU144A_SOM_Power (R5.2)
MCU_ADCIN_A0A1_N: MCU144A_ADC (U1.P1), MCU144A_Baseboard_Connectors (J1.117)
MCU_ADCIN_A0A1_P: MCU144A_ADC (U1.R1), MCU144A_Baseboard_Connectors (J1.119)
MCU_ADCIN_A2A3_N: MCU144A_ADC (U1.M2), MCU144A_Baseboard_Connectors (J2.118)
MCU_ADCIN_A2A3_P: MCU144A_ADC (U1.M1), MCU144A_Baseboard_Connectors (J2.120)
MCU_ADCIN_A4A5_N: MCU144A_ADC (U1.L1), MCU144A_Baseboard_Connectors (J2.117)
MCU_ADCIN_A4A5_P: MCU144A_ADC (U1.L2), MCU144A_Baseboard_Connectors (J2.119)
MCU_ADCIN_A6A7_N: MCU144A_ADC (U1.K5), MCU144A_Baseboard_Connectors (J1.118)
MCU_ADCIN_A6A7_P: MCU144A_ADC (U1.L5), MCU144A_Baseboard_Connectors (J1.120)
MCU_ADCIN_A8A9_N: MCU144A_ADC (U1.H3), MCU144A_Baseboard_Connectors (J1.113)
MCU_ADCIN_A8A9_P: MCU144A_ADC (U1.H4), MCU144A_Baseboard_Connectors (J1.115)
MCU_ADCIN_A10A11_N: MCU144A_ADC (U1.G4), MCU144A_Baseboard_Connectors (J2.98)
MCU_ADCIN_A10A11_P: MCU144A_ADC (U1.G3), MCU144A_Baseboard_Connectors (J2.100)
MCU_ADCIN_A12A13_N: MCU144A_ADC (U1.K1), MCU144A_Baseboard_Connectors (J2.110)
MCU_ADCIN_A12A13_P: MCU144A_ADC (U1.K2), MCU144A_Baseboard_Connectors (J2.112)
MCU_ADCIN_A14A15_N: MCU144A_ADC (U1.M4), MCU144A_Baseboard_Connectors (J1.90)
MCU_ADCIN_A14A15_P: MCU144A_ADC (U1.M3), MCU144A_Baseboard_Connectors (J1.92)
MCU_ADCIN_B0B1_N: MCU144A_ADC (U1.N3), MCU144A_Baseboard_Connectors (J1.114)
MCU_ADCIN_B0B1_P: MCU144A_ADC (U1.P2), MCU144A_Baseboard_Connectors (J1.116)
MCU_ADCIN_B2B3_N: MCU144A_ADC (U1.L3), MCU144A_Baseboard_Connectors (J1.109)
MCU_ADCIN_B2B3_P: MCU144A_ADC (U1.L4), MCU144A_Baseboard_Connectors (J1.111)
MCU_ADCIN_B4B5_N: MCU144A_ADC (U1.K3), MCU144A_Baseboard_Connectors (J1.110)
MCU_ADCIN_B4B5_P: MCU144A_ADC (U1.K4), MCU144A_Baseboard_Connectors (J1.112)
MCU_ADCIN_B6B7_N: MCU144A_ADC (U1.H5), MCU144A_Baseboard_Connectors (J2.97)
MCU_ADCIN_B6B7_P: MCU144A_ADC (U1.J5), MCU144A_Baseboard_Connectors (J2.99)
MCU_ADCIN_B12B13_N: MCU144A_ADC (U1.J1), MCU144A_Baseboard_Connectors (J2.114)
MCU_ADCIN_B12B13_P: MCU144A_ADC (U1.J2), MCU144A_Baseboard_Connectors (J2.116)
MCU_ADCIN_B16B17_N: MCU144A_ADC (U1.J3), MCU144A_Baseboard_Connectors (J2.113)
MCU_ADCIN_B16B17_P: MCU144A_ADC (U1.J4), MCU144A_Baseboard_Connectors (J2.115)
MCU_ADCIN_C0: MCU144A_ADC (U1.R2), MCU144A_Baseboard_Connectors (J1.106)
MCU_ADCIN_C1: MCU144A_ADC (U1.T2), MCU144A_Baseboard_Connectors (J1.103)
MCU_ADCIN_C2: MCU144A_ADC (U1.N4), MCU144A_Baseboard_Connectors (J1.101)
MCU_ADCIN_C3: MCU144A_ADC (U1.M5), MCU144A_Baseboard_Connectors (J2.111)
MCU_ADCIN_C4: MCU144A_ADC (U1.P5), MCU144A_Baseboard_Connectors (J2.109)
MCU_ADCIN_C5: MCU144A_ADC (U1.N5), MCU144A_Baseboard_Connectors (J2.108)
MCU_ADCIN_C11: MCU144A_ADC (U1.P8), MCU144A_Baseboard_Connectors (J2.107)
MCU_ADCIN_C12: MCU144A_ADC (U1.R8), MCU144A_Baseboard_Connectors (J1.107)
MCU_ADCIN_C13: MCU144A_ADC (U1.T8), MCU144A_Baseboard_Connectors (J2.106)
MCU_ADCIN_C16: MCU144A_ADC (U1.N7), MCU144A_Baseboard_Connectors (J1.105)
MCU_ADCIN_C17: MCU144A_ADC (U1.P7), MCU144A_Baseboard_Connectors (J1.108)
MCU_ADCIN_D0: MCU144A_ADC (U1.R3), MCU144A_Baseboard_Connectors (J1.104)
MCU_ADCIN_D1: MCU144A_ADC (U1.T3), MCU144A_Baseboard_Connectors (J1.102)
MCU_ADCIN_D2: MCU144A_ADC (U1.R5), MCU144A_Baseboard_Connectors (J1.99)
MCU_ADCIN_D3: MCU144A_ADC (U1.R6), MCU144A_Baseboard_Connectors (J1.97)
MCU_ADCIN_D10: MCU144A_ADC (U1.N6), MCU144A_Baseboard_Connectors (J1.100)
MCU_ADCIN_D11: MCU144A_ADC (U1.P6), MCU144A_Baseboard_Connectors (J1.98)
MCU_ADCIN_D12: MCU144A_ADC (U1.M7), MCU144A_Baseboard_Connectors (J2.105)
MCU_ADCIN_D13: MCU144A_ADC (U1.M6), MCU144A_Baseboard_Connectors (J2.104)
MCU_ADCIN_D16: MCU144A_ADC (U1.R7), MCU144A_Baseboard_Connectors (J2.103)
MCU_ADCIN_D17: MCU144A_ADC (R70.1), MCU144A_SOM_Power (U2.32)
MCU_ADCIN_E0: MCU144A_ADC (U1.P3), MCU144A_Baseboard_Connectors (J1.95)
MCU_ADCIN_E1: MCU144A_ADC (U1.P4), MCU144A_Baseboard_Connectors (J1.93)
MCU_ADCIN_E2: MCU144A_ADC (U1.T5), MCU144A_Baseboard_Connectors (J1.96)
MCU_ADCIN_E3: MCU144A_ADC (U1.T6), MCU144A_Baseboard_Connectors (J1.94)
MCU_ADCIN_E10: MCU144A_ADC (U1.R10), MCU144A_Baseboard_Connectors (J1.91)
MCU_ADCIN_E12: MCU144A_ADC (U1.P9), MCU144A_Baseboard_Connectors (J1.89)
MCU_AIO186: MCU144A_ADC (U1.N8), MCU144A_Baseboard_Connectors (J1.54)
MCU_AIO206: MCU144A_ADC (U1.T10), MCU144A_Baseboard_Connectors (J2.27)
MCU_AIO207: MCU144A_ADC (U1.T9), MCU144A_Baseboard_Connectors (J2.25)
MCU_AIO209: MCU144A_ADC (U1.R9), MCU144A_Baseboard_Connectors (J2.29)
MCU_AIO211: MCU144A_ADC (U1.N9), MCU144A_Baseboard_Connectors (J1.52)
MCU_AIO212: MCU144A_ADC (U1.P10), MCU144A_Baseboard_Connectors (J1.48)
MCU_AIO213: MCU144A_ADC (U1.T11), MCU144A_Baseboard_Connectors (J1.50)
MCU_CANRX: MCU144A_GPIO_Power (R45.1 R54.1), MCU144A_Baseboard_Connectors (J1.37)
MCU_CANTX: MCU144A_GPIO_Power (R26.1 R27.1), MCU144A_Baseboard_Connectors (J1.35)
MCU_ERRORSTS: MCU144A_Clock_Reset_Boot (R44.2 TP13.1 U1.M16), MCU144A_SOM_Power (U2.18)
MCU_ESC_RX1_DATA1: MCU144A_GPIO_Power (R25.1), MCU144A_Baseboard_Connectors (J3.80)
MCU_ESC_RX1_DATA2: MCU144A_GPIO_Power (R29.1), MCU144A_Baseboard_Connectors (J3.82)
MCU_GPIO0: MCU144A_GPIO_Power (U1.A8), MCU144A_Baseboard_Connectors (J1.15)
MCU_GPIO1: MCU144A_GPIO_Power (U1.A7), MCU144A_Baseboard_Connectors (J1.13)
MCU_GPIO2: MCU144A_GPIO_Power (U1.B7), MCU144A_Baseboard_Connectors (J1.11)
MCU_GPIO3: MCU144A_GPIO_Power (U1.C7), MCU144A_Baseboard_Connectors (J1.9)
MCU_GPIO4: MCU144A_GPIO_Power (U1.D7), MCU144A_Baseboard_Connectors (J1.7)
MCU_GPIO5: MCU144A_GPIO_Power (U1.A6), MCU144A_Baseboard_Connectors (J1.5)
MCU_GPIO9: MCU144A_GPIO_Power (U1.A5), MCU144A_Clock_Reset_Boot (LED4.2), MCU144A_Baseboard_Connectors (J1.73)
MCU_GPIO10: MCU144A_GPIO_Power (R3.1 U1.C5), MCU144A_Baseboard_Connectors (J1.64)
MCU_GPIO11: MCU144A_GPIO_Power (U1.A4), MCU144A_Baseboard_Connectors (J3.116)
MCU_GPIO12: MCU144A_GPIO_Power (U1.A3), MCU144A_Baseboard_Connectors (J1.16)
MCU_GPIO13: MCU144A_GPIO_Power (U1.A2), MCU144A_Baseboard_Connectors (J1.14)
MCU_GPIO14: MCU144A_GPIO_Power (U1.B3), MCU144A_Baseboard_Connectors (J2.59)
MCU_GPIO15: MCU144A_GPIO_Power (U1.C4), MCU144A_Baseboard_Connectors (J1.68)
MCU_GPIO17: MCU144A_GPIO_Power (U1.B2), MCU144A_Baseboard_Connectors (J1.10)
MCU_GPIO18: MCU144A_GPIO_Power (R23.1 U1.F2), MCU144A_Baseboard_Connectors (J1.66)
MCU_GPIO19: MCU144A_GPIO_Power (U1.B1), MCU144A_Baseboard_Connectors (J2.54)
MCU_GPIO20: MCU144A_GPIO_Power (U1.C1), MCU144A_Baseboard_Connectors (J1.8)
MCU_GPIO21: MCU144A_GPIO_Power (U1.C2), MCU144A_Baseboard_Connectors (J1.6)
MCU_GPIO22: MCU144A_GPIO_Power (R24.1 U1.F1), MCU144A_Baseboard_Connectors (J1.62)
MCU_GPIO23: MCU144A_GPIO_Power (U1.B8), MCU144A_Clock_Reset_Boot (LED3.2), MCU144A_Baseboard_Connectors (J1.75)
MCU_GPIO24: MCU144A_GPIO_Power (U1.C8), MCU144A_Baseboard_Connectors (J3.100)
MCU_GPIO25: MCU144A_GPIO_Power (U1.D8), MCU144A_Baseboard_Connectors (J3.113)
MCU_GPIO26: MCU144A_GPIO_Power (U1.B9), MCU144A_Baseboard_Connectors (J1.4)
MCU_GPIO27: MCU144A_GPIO_Power (U1.C9), MCU144A_Baseboard_Connectors (J1.3)
MCU_GPIO28: MCU144A_GPIO_Power (U1.D9), MCU144A_Baseboard_Connectors (J1.1)
MCU_GPIO29: MCU144A_GPIO_Power (U1.A9), MCU144A_Baseboard_Connectors (J3.107)
MCU_GPIO30: MCU144A_GPIO_Power (U1.A10), MCU144A_Baseboard_Connectors (J3.109)
MCU_GPIO31: MCU144A_GPIO_Power (U1.B10), MCU144A_Baseboard_Connectors (J2.50)
MCU_GPIO32: MCU144A_GPIO_Power (U1.G16), MCU144A_Baseboard_Connectors (J1.63)
MCU_GPIO33: MCU144A_GPIO_Power (U1.P14), MCU144A_Baseboard_Connectors (J1.61)
MCU_GPIO34: MCU144A_GPIO_Power (U1.D1), MCU144A_Baseboard_Connectors (J1.65)
MCU_GPIO35: MCU144A_GPIO_Power (U1.E1), MCU144A_Baseboard_Connectors (J1.42)
MCU_GPIO36: MCU144A_GPIO_Power (U1.N14), MCU144A_Baseboard_Connectors (J1.69)
MCU_GPIO37: MCU144A_GPIO_Power (U1.R16), MCU144A_Baseboard_Connectors (J1.67)
MCU_GPIO38: MCU144A_GPIO_Power (U1.E14), MCU144A_Baseboard_Connectors (J3.104)
MCU_GPIO39: MCU144A_GPIO_Power (U1.P15), MCU144A_Baseboard_Connectors (J3.99)
MCU_GPIO40: MCU144A_GPIO_Power (U1.P16), MCU144A_Baseboard_Connectors (J1.76), MCU144A_Emulation_Connectors (J4.16)
MCU_GPIO41: MCU144A_GPIO_Power (U1.N15), MCU144A_Baseboard_Connectors (J1.74)
MCU_GPIO42: MCU144A_GPIO_Power (U1.C16), MCU144A_Baseboard_Connectors (J1.31), MCU144A_Emulation_Connectors (J4.10)
MCU_GPIO43: MCU144A_GPIO_Power (U1.C15), MCU144A_Baseboard_Connectors (J1.33), MCU144A_Emulation_Connectors (J4.9)
MCU_GPIO44: MCU144A_GPIO_Power (U1.G14), MCU144A_Baseboard_Connectors (J3.88)
MCU_GPIO45: MCU144A_GPIO_Power (U1.G15), MCU144A_Baseboard_Connectors (J3.91)
MCU_GPIO46: MCU144A_GPIO_Power (U1.D14), MCU144A_Baseboard_Connectors (J1.36)
MCU_GPIO47: MCU144A_GPIO_Power (U1.D15), MCU144A_Baseboard_Connectors (J1.38)
MCU_GPIO48: MCU144A_GPIO_Power (U1.N16), MCU144A_Baseboard_Connectors (J2.31)
MCU_GPIO52: MCU144A_GPIO_Power (U1.L14), MCU144A_Baseboard_Connectors (J2.52)
MCU_GPIO53: MCU144A_GPIO_Power (U1.L15), MCU144A_Baseboard_Connectors (J1.57)
MCU_GPIO54: MCU144A_GPIO_Power (U1.L16), MCU144A_Clock_Reset_Boot (R31.2 R35.2)
MCU_GPIO55: MCU144A_GPIO_Power (U1.K13), MCU144A_Baseboard_Connectors (J3.87)
MCU_GPIO56: MCU144A_GPIO_Power (U1.K14), MCU144A_Baseboard_Connectors (J2.60)
MCU_GPIO57: MCU144A_GPIO_Power (U1.K15), MCU144A_Baseboard_Connectors (J2.58)
MCU_GPIO58: MCU144A_GPIO_Power (U1.K16), MCU144A_Baseboard_Connectors (J1.45), MCU144A_Emulation_Connectors (J4.14)
MCU_GPIO59: MCU144A_GPIO_Power (U1.J16), MCU144A_Baseboard_Connectors (J1.43), MCU144A_Emulation_Connectors (J4.15)
MCU_GPIO60: MCU144A_GPIO_Power (U1.J15), MCU144A_Baseboard_Connectors (J1.41), MCU144A_Emulation_Connectors (J4.13)
MCU_GPIO61: MCU144A_GPIO_Power (U1.J13), MCU144A_Baseboard_Connectors (J1.39)
MCU_GPIO62: MCU144A_GPIO_Power (U1.H13), MCU144A_Baseboard_Connectors (J3.97)
MCU_GPIO63: MCU144A_GPIO_Power (U1.H14), MCU144A_Baseboard_Connectors (J3.78)
MCU_GPIO66: MCU144A_GPIO_Power (U1.G13), MCU144A_Baseboard_Connectors (J3.84)
MCU_GPIO69: MCU144A_GPIO_Power (U1.A15), MCU144A_Baseboard_Connectors (J3.76)
MCU_GPIO70: MCU144A_GPIO_Power (U1.C14), MCU144A_Baseboard_Connectors (J3.93)
MCU_GPIO71: MCU144A_GPIO_Power (U1.B14), MCU144A_Baseboard_Connectors (J3.95)
MCU_GPIO72: MCU144A_GPIO_Power (U1.A14), MCU144A_Clock_Reset_Boot (R42.2), MCU144A_Baseboard_Connectors (J3.96)
MCU_GPIO73: MCU144A_GPIO_Power (U1.E13), MCU144A_Baseboard_Connectors (J3.94)
MCU_GPIO74: MCU144A_GPIO_Power (U1.D13), MCU144A_Baseboard_Connectors (J3.92)
MCU_GPIO75: MCU144A_GPIO_Power (U1.C13), MCU144A_Baseboard_Connectors (J3.90)
MCU_GPIO77: MCU144A_GPIO_Power (U1.A13), MCU144A_Baseboard_Connectors (J2.26)
MCU_GPIO78: MCU144A_GPIO_Power (U1.D12), MCU144A_Baseboard_Connectors (J2.56)
MCU_GPIO79: MCU144A_GPIO_Power (U1.C12), MCU144A_Baseboard_Connectors (J3.111)
MCU_GPIO80: MCU144A_GPIO_Power (U1.B12), MCU144A_Baseboard_Connectors (J3.102)
MCU_GPIO81: MCU144A_GPIO_Power (U1.A12), MCU144A_SOM_Power (R15.2), MCU144A_Baseboard_Connectors (R79.2)
MCU_GPIO82: MCU144A_GPIO_Power (U1.D10), MCU144A_Baseboard_Connectors (J3.106)
MCU_GPIO83: MCU144A_GPIO_Power (U1.A11), MCU144A_Baseboard_Connectors (J3.108)
MCU_GPIO84: MCU144A_GPIO_Power (U1.D11), MCU144A_Clock_Reset_Boot (R43.1), MCU144A_Baseboard_Connectors (J3.115)
MCU_GPIO85: MCU144A_GPIO_Power (U1.B11), MCU144A_Baseboard_Connectors (J3.112)
MCU_GPIO86: MCU144A_GPIO_Power (U1.C11), MCU144A_Baseboard_Connectors (J2.28)
MCU_GPIO87: MCU144A_GPIO_Power (U1.C10), MCU144A_Baseboard_Connectors (J3.114)
MCU_GPIO88: MCU144A_GPIO_Power (U1.C3), MCU144A_Baseboard_Connectors (J1.2)
MCU_GPIO89: MCU144A_GPIO_Power (U1.D4), MCU144A_Baseboard_Connectors (J3.118)
MCU_GPIO90: MCU144A_GPIO_Power (U1.D3), MCU144A_Baseboard_Connectors (J3.120)
MCU_GPIO91: MCU144A_GPIO_Power (U1.D2), MCU144A_SOM_Power (U2.35), MCU144A_Baseboard_Connectors (J2.30)
MCU_GPIO92: MCU144A_GPIO_Power (U1.E2), MCU144A_SOM_Power (U2.34), MCU144A_Baseboard_Connectors (J2.32)
MCU_GPIO93: MCU144A_GPIO_Power (U1.E3), MCU144A_SOM_Power (U2.33), MCU144A_Baseboard_Connectors (J2.34)
MCU_GPIO94: MCU144A_GPIO_Power (U1.E4), MCU144A_Baseboard_Connectors (J2.36)
MCU_GPIO95: MCU144A_GPIO_Power (U1.E5), MCU144A_Baseboard_Connectors (J1.70)
MCU_GPIO96: MCU144A_GPIO_Power (U1.F3), MCU144A_Baseboard_Connectors (J2.46)
MCU_GPIO97: MCU144A_GPIO_Power (U1.F4), MCU144A_Baseboard_Connectors (J1.46)
MCU_GPIO98: MCU144A_GPIO_Power (U1.F5), MCU144A_Baseboard_Connectors (J1.44)
MCU_GPIO99: MCU144A_GPIO_Power (R4.1 U1.G5), MCU144A_SOM_Power (R71.1)
MCU_GPIO100: MCU144A_GPIO_Power (U1.B4), MCU144A_Baseboard_Connectors (J1.12)
MCU_GPIO101: MCU144A_GPIO_Power (U1.B5), MCU144A_Baseboard_Connectors (J2.48)
MCU_GPIO103: MCU144A_GPIO_Power (U1.D16), MCU144A_Baseboard_Connectors (J1.59)
MCU_GPIO105: MCU144A_GPIO_Power (U1.J14), MCU144A_Baseboard_Connectors (J1.55)
MCU_GPIO127: MCU144A_GPIO_Power (U1.F13), MCU144A_Baseboard_Connectors (J3.63)
MCU_GPIO221: MCU144A_Clock_Reset_Boot (U1.F16), MCU144A_Baseboard_Connectors (J2.57)
MCU_GPIO222: MCU144A_Clock_Reset_Boot (R39.1 U1.T14), MCU144A_Baseboard_Connectors (J1.19), MCU144A_Emulation_Connectors (J4.5 R63.1)
MCU_GPIO223: MCU144A_Clock_Reset_Boot (R40.1 U1.R14), MCU144A_Baseboard_Connectors (J1.21), MCU144A_Emulation_Connectors (J4.6 R62.1)
MCU_GPIO232: MCU144A_ADC (U1.H2), MCU144A_Baseboard_Connectors (J1.40)
MCU_GPIO233: MCU144A_ADC (U1.H1), MCU144A_Baseboard_Connectors (J3.89)
MCU_GPIO234: MCU144A_ADC (U1.G2), MCU144A_Baseboard_Connectors (J2.23)
MCU_GPIO235: MCU144A_ADC (U1.G1), MCU144A_Baseboard_Connectors (J2.21)
MCU_GPIO236: MCU144A_ADC (U1.M8), MCU144A_Baseboard_Connectors (J2.55)
MCU_GPIO237: MCU144A_ADC (U1.M9), MCU144A_Baseboard_Connectors (J2.53)
MCU_GPIO238: MCU144A_ADC (U1.N12), MCU144A_Baseboard_Connectors (J1.58)
MCU_GPIO239: MCU144A_ADC (U1.P12), MCU144A_Baseboard_Connectors (J1.71)
MCU_GPIO240: MCU144A_ADC (U1.N10), MCU144A_Baseboard_Connectors (J3.103)
MCU_GPIO241: MCU144A_ADC (U1.N11), MCU144A_Baseboard_Connectors (J3.105)
MCU_GPIO242: MCU144A_ADC (U1.T12), MCU144A_Baseboard_Connectors (J1.56)
MCU_GPIO243: MCU144A_ADC (U1.R12), MCU144A_Baseboard_Connectors (J3.83)
MCU_GPIO244: MCU144A_ADC (U1.R13), MCU144A_Baseboard_Connectors (J3.85)
MCU_GPIO245: MCU144A_ADC (U1.T13), MCU144A_Baseboard_Connectors (J3.101)
MCU_GPIO246: MCU144A_ADC (U1.P11), MCU144A_Baseboard_Connectors (J1.60)
MCU_GPIO247: MCU144A_ADC (U1.R11), MCU144A_Baseboard_Connectors (J3.59)
MCU_GPIO248: MCU144A_ADC (U1.P13), MCU144A_Baseboard_Connectors (J2.35)
MCU_GPIO249: MCU144A_ADC (U1.N13), MCU144A_Baseboard_Connectors (J2.33)
MCU_TCK: MCU144A_Clock_Reset_Boot (U1.R15), MCU144A_Baseboard_Connectors (J1.22), MCU144A_Emulation_Connectors (J4.4 R61.1)
MCU_TMS: MCU144A_Clock_Reset_Boot (R41.1 U1.T15), MCU144A_Baseboard_Connectors (J1.24), MCU144A_Emulation_Connectors (J4.3 R60.1)
MCU_XRSn: MCU144A_Clock_Reset_Boot (6 pins), MCU144A_SOM_Power (R16.1 U2.13), MCU144A_Baseboard_Connectors (J1.29), MCU144A_Emulation_Connectors (R64.1)
PMIC_COMP1_IN+: MCU144A_SOM_Power (U2.21), MCU144A_Baseboard_Connectors (J3.37)
PMIC_COMP1_IN-: MCU144A_SOM_Power (U2.24), MCU144A_Baseboard_Connectors (J3.35)
PMIC_COMP2_IN+: MCU144A_SOM_Power (U2.28), MCU144A_Baseboard_Connectors (J3.33)
PMIC_COMP2_IN-: MCU144A_SOM_Power (U2.25), MCU144A_Baseboard_Connectors (J3.31)
PMIC_SAFE_OUT1: MCU144A_SOM_Power (R15.1 U2.31), MCU144A_Baseboard_Connectors (R1.1 R2.2 R74.2)
PMIC_SAFE_OUT2: MCU144A_SOM_Power (R10.1 R11.2 U2.27), MCU144A_Baseboard_Connectors (J3.29)
PMIC_WAKE1: MCU144A_SOM_Power (R66.1 U2.6), MCU144A_Baseboard_Connectors (J1.30)
PMIC_WAKE2: MCU144A_SOM_Power (U2.43), MCU144A_Baseboard_Connectors (J3.39)
SOM_GPIO6: MCU144A_GPIO_Power (R88.1), MCU144A_Baseboard_Connectors (J3.67)
SOM_GPIO7: MCU144A_GPIO_Power (R94.1), MCU144A_Baseboard_Connectors (J3.69)
SOM_GPIO8: MCU144A_GPIO_Power (R55.1), MCU144A_Baseboard_Connectors (J3.71)
SOM_GPIO16: MCU144A_GPIO_Power (R81.1), MCU144A_Baseboard_Connectors (J3.65)
SOM_GPIO49: MCU144A_GPIO_Power (R86.1), MCU144A_Baseboard_Connectors (J1.53)
SOM_GPIO50: MCU144A_GPIO_Power (R93.1), MCU144A_Baseboard_Connectors (J1.51)
SOM_GPIO51: MCU144A_GPIO_Power (R52.1), MCU144A_Baseboard_Connectors (J1.49)
SOM_GPIO76: MCU144A_GPIO_Power (R89.1), MCU144A_Baseboard_Connectors (J3.61)
VREFHIAB: MCU144A_ADC (S3.4), MCU144A_Baseboard_Connectors (J1.85)
VREFHICDE: MCU144A_ADC (S4.4), MCU144A_Baseboard_Connectors (J1.83)

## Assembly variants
001: not fitted C96 C98 FID1 FID2 FID3 FID4 FID5 FID6 R1 R2 R3 R5 R10 R11 R15 R16 R21 R23 R24 R26 R30 R31 R35 R37 R44 R45 R49 R50 R68 R82 R83 R84 R90 R91 R92 R95 R96
002: not fitted C96 C98 FID1 FID2 FID3 FID4 FID5 FID6 R1 R2 R3 R5 R10 R11 R15 R16 R21 R23 R24 R26 R30 R31 R35 R37 R44 R45 R46 R49 R50 R68 R82 R83 R84 R90 R91 R92 R95 R96
003: not fitted C96 C98 FID1 FID2 FID3 FID4 FID5 FID6 R1 R2 R3 R5 R10 R11 R15 R16 R21 R23 R24 R26 R31 R33 R35 R37 R44 R45 R46 R49 R50 R68 R82 R83 R84 R90 R91 R92 R95 R96
004: not fitted C96 C98 FID1 FID2 FID3 FID4 FID5 FID6 R1 R2 R3 R5 R10 R11 R15 R16 R21 R23 R24 R26 R31 R33 R35 R37 R44 R45 R46 R49 R50 R68 R82 R83 R84 R90 R91 R92 R95 R96; alternate parts L1 -> CMP-0003428-2
F29 Required Circuitry Only: not fitted !PCB1 C40 C43 C44 C45 C46 C47 C48 C49 C50 C51 C61 C67 C69 C70 C71 C72 C73 C74 C75 C77 C78 C79 C83 C84 C85 C86 C87 C96 C98 FID1 FID2 FID3 FID4 FID5 FID6 J1 J2 J3 J4 J5 L5 LED1 LED2 LED3 LED4 Logo1 Logo2 Logo3 Logo4 MH1 MH2 MH3 MH4 R1 R2 R3 R5 R10 R11 R12 R13 R14 R15 R16 R17 R18 R19 R20 R21 R23 R24 R25 R26 R27 R29 R30 R31 R32 R33 R34 R35 R36 R37 R38 R44 R45 R46 R47 R48 R49 R50 R52 R53 R54 R55 R59 R60 R61 R62 R63 R64 R65 R67 R68 R69 R74 R79 R80 R81 R82 R83 R84 R85 R86 R87 R88 R89 R90 R91 R92 R93 R94 R95 R96 R97 S3 S4 SW1 TP1 TP2 TP3 TP4 TP5 TP6 TP7 TP8 TP9 TP10 TP11 TP12 TP13 TP14 TP15 TP16 TP17 U3 U4 U5 U6 U8 Y1 ZZ1 ZZ2 ZZ3 ZZ4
